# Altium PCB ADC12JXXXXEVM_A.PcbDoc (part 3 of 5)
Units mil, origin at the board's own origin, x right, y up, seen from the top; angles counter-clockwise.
Board outline 5739 x 2680 mil, 10 copper layers (Top Layer L1, Gnd-Plane - L2, Signals - L3, Gnd-Plane - L4, Pwr Plane - L5, Signals - L6, Gnd-Plane - L7, Signals - L8, Gnd-Plane - L9, Bottom Layer - L10), stack 57.8 mil thick; 582 components, 343 nets, 1924 pads, 1319 vias.

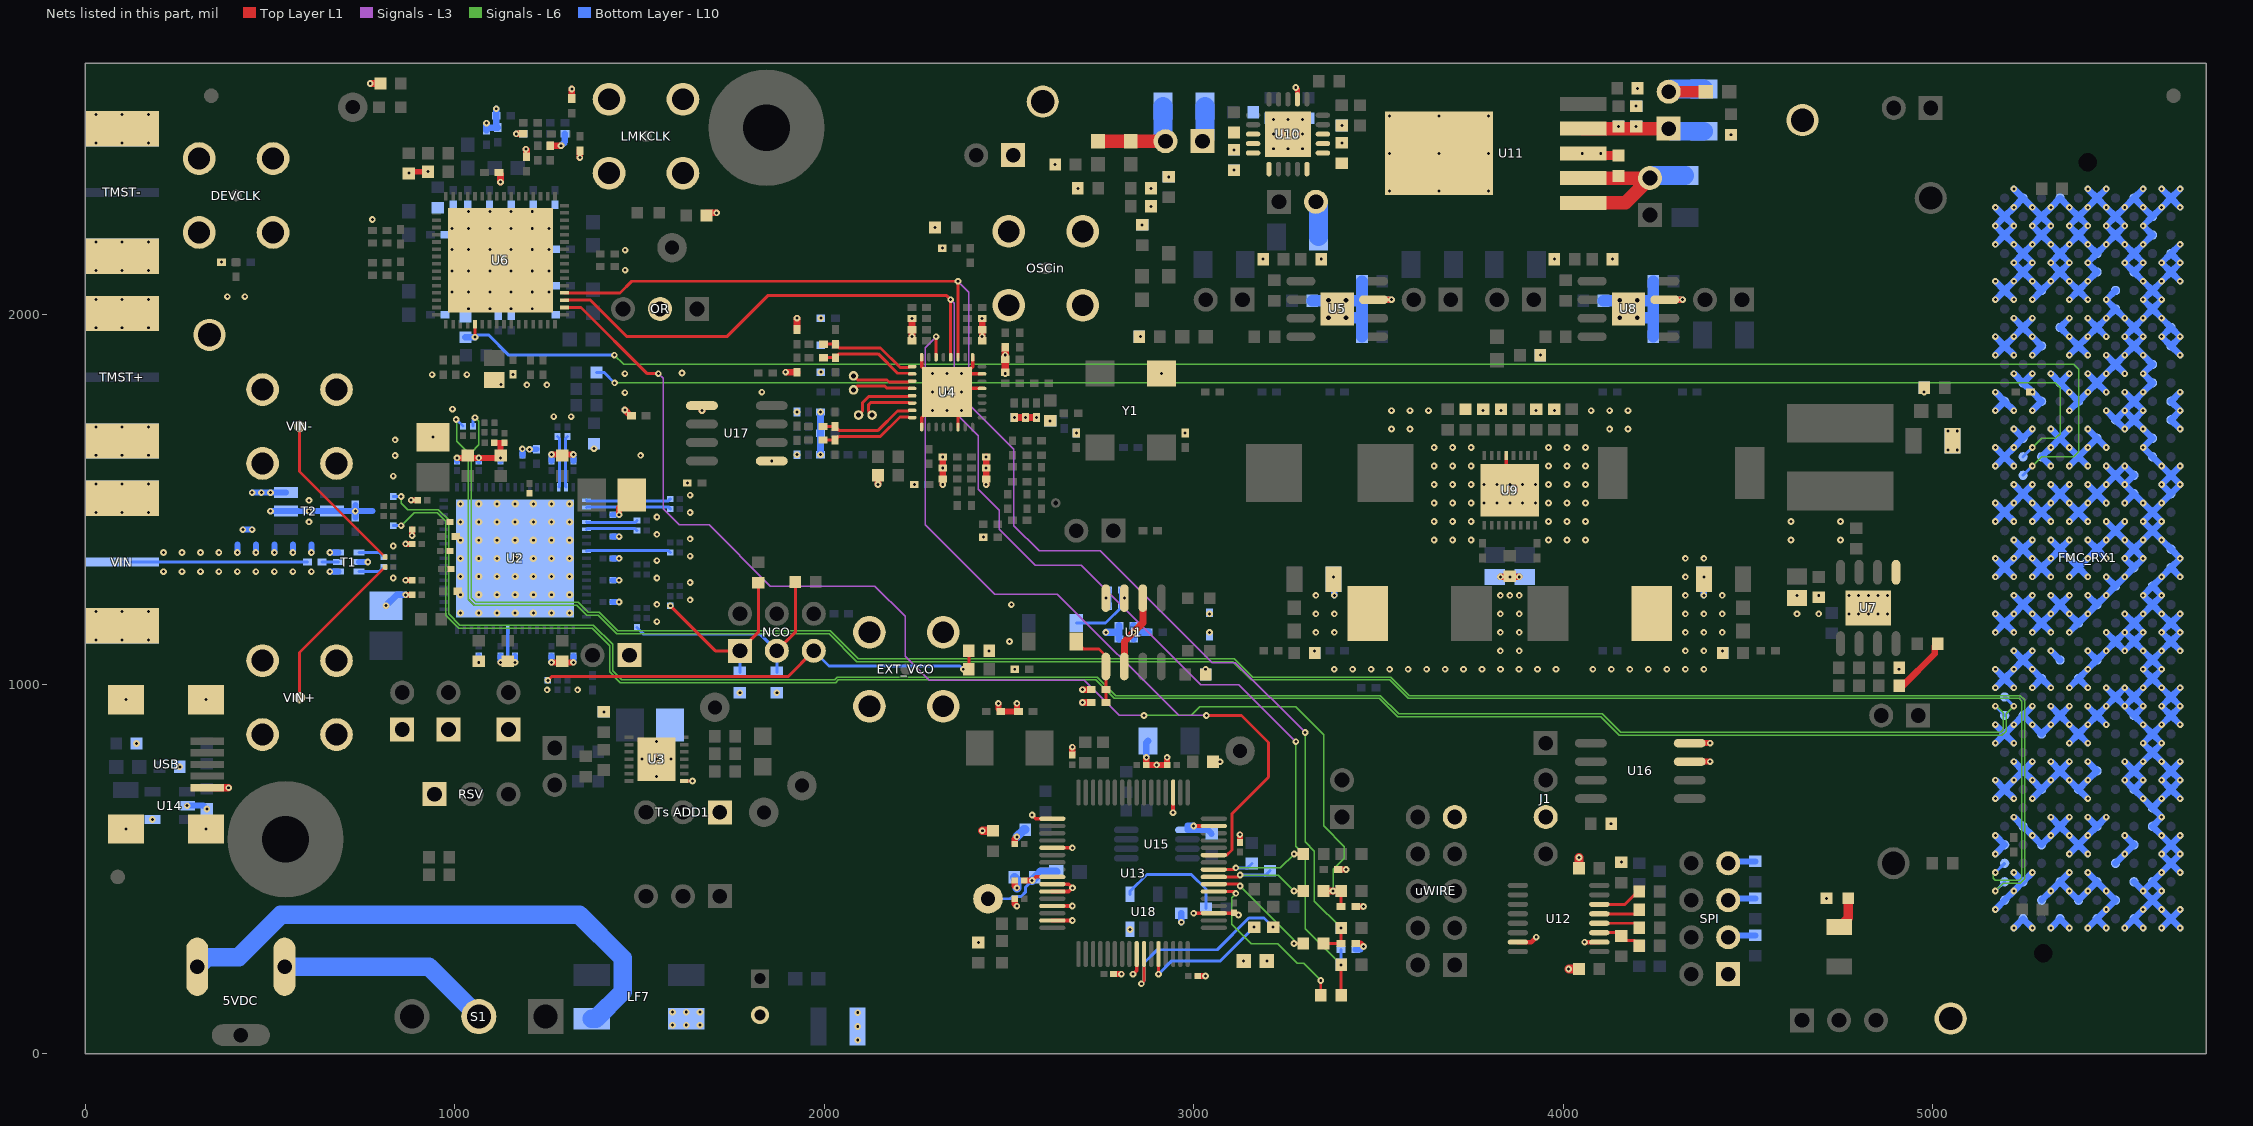
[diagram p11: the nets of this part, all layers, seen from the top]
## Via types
v1: diameter 18, hole 8, Top Layer L1 to Bottom Layer - L10, tented both sides, 1099 vias
v2: diameter 19.68, hole 7.87, Top Layer L1 to Bottom Layer - L10, 99 vias
v3: diameter 18, hole 8, Top Layer L1 to Bottom Layer - L10, tented bottom, 58 vias
v4: diameter 18, hole 8, Top Layer L1 to Bottom Layer - L10, tented top, 48 vias
v5: diameter 25.98, hole 12.99, Top Layer L1 to Bottom Layer - L10, tented top, 8 vias
v6: diameter 19.68, hole 7.87, Top Layer L1 to Bottom Layer - L10, tented top, 5 vias
v7: diameter 126, hole 106, Top Layer L1 to Bottom Layer - L10, tented top, 2 vias

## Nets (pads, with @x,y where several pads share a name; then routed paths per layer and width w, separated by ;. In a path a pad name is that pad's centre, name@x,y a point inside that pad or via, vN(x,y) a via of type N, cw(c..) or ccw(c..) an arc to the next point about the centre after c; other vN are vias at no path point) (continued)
FMC_DEVCLK_N: C93.2 FMC_RX1.K29 | length 4941.1
  Signals - L6 w4: v1(854.84,1507.44) 854.84,1489.67 872.56,1471.95 955.63,1471.95 983.08,1444.5 983.08,1190.03 1014.11,1159 1375.31,1159 1427,1107.31 1427,1036.2 1451.2,1012 2027.99,1012 2034.99,1019 2738,1019 2788,969 3505,969 3555,919 4105,919 4155,869 5183,869 5190,876 5190,923 5173,940 v3(5169,940)
  Bottom Layer - L10 w8: C93.2@833.57,1507.44 v1(854.84,1507.44) ; v3(5169,940) FMC_RX1.K29@5194,915
FMC_DEVCLK_P: C92.2 FMC_RX1.K28 | length 4941.6
  Signals - L6 w4: v1(854.84,1428.47) 890.32,1463.95 952.31,1463.95 975.08,1441.18 975.08,1186.71 1010.8,1151 1372,1151 1419,1104 1419,1032.89 1447.89,1004 2031.3,1004 2038.3,1011 2734.69,1011 2784.69,961 3501.69,961 3551.69,911 4101.69,911 4151.69,861 5186.31,861 5198,872.69 5198,919 v3(5219,940)
  Bottom Layer - L10 w8: C92.2@833.57,1428.47 v1(854.84,1428.47) ; FMC_RX1.K28@5194,965 v3(5219,940)
FMC_SYSREF_N: C91.2 FMC_RX1.K38 | length 5456.4
  Signals - L6 w4: v1(1054.96,1720.97) 1064.96,1710.97 1064.96,1647 1044.35,1626.39 1044.35,1233.09 1056.47,1220.97 1333.83,1220.97 1360.63,1194.16 1391.25,1194.16 1441.42,1144 2016.62,1144 2091.61,1069 3109,1069 3159,1019 3533,1019 3583,969 5236.31,969 5248,957.31 5248,472.69 5236.31,461 5190,461 v3(5169,440)
  Bottom Layer - L10 w8: C91.2@1048.93,1697.99 1048.93,1714.94 v1(1054.96,1720.97) ; v3(5169,440) FMC_RX1.K38@5194,465
FMC_SYSREF_P: C90.2 FMC_RX1.K37 | length 5456.2
  Signals - L6 w4: v1(1003.93,1715.99) 1005.9,1714.02 1005.9,1656.84 1036.35,1626.39 1036.35,1229.77 1053.16,1212.97 1330.51,1212.97 1357.32,1186.16 1387.94,1186.16 1438.1,1136 2013.3,1136 2088.3,1061 3105.69,1061 3155.69,1011 3529.69,1011 3579.69,961 5233,961 5240,954 5240,476 5233,469 5169,469 5163,475 5163,484 v3(5169,490)
  Bottom Layer - L10 w8: v1(1003.93,1715.99) C90.2@1021.93,1697.99 ; v3(5169,490) FMC_RX1.K37@5194,515
FTDI_ADC_SCLK: R109.2 U12.14 | length 122.5
  Top Layer L1 w8: U12.14@4097.24,403.91 4166.85,403.91 4201.44,438.5 R109.2@4205.44,438.5
FTDI_ADC_SCSB: R118.2 R123.1 U12.11 | length 123
  Top Layer L1 w8: U12.11@4097.24,327.14 4147.94,327.14 R123.1@4157,318.09 4168.56,306.53 4190.41,306.53 R118.2@4205.44,291.5
FTDI_ADC_SDI: R111.2 U12.13 | length 112.8
  Top Layer L1 w8: U12.13@4097.24,378.32 4194.26,378.32 R111.2@4205.44,389.5
FTDI_ADC_SDO: R110.2 U12.12 | length 113.3
  Top Layer L1 w8: U12.12@4097.24,352.73 4193.21,352.73 R110.2@4205.44,340.5
FTDI_LMK_CSB: R68.2 R130.2 U13.40 | length 347.3
  Top Layer L1 w8: U13.40@3053.98,478.16 3120.45,478.16 v1(3125.45,483.16) ; v1(3270.88,440) R68.2@3295.88,440
  Signals - L6 w4: v1(3125.45,483.16) 3227.72,483.16 v1(3270.88,440)
  Bottom Layer - L10 w8: v1(3125.45,483.16) 3194.25,483.16 R130.2@3206,494.9
FTDI_LMK_TRF_CLK: R115.2 U13.38 | length 494.8
  Top Layer L1 w8: U13.38@3053.98,438.79 3108.45,438.79 v1(3113.44,433.79) ; R115.2@3343.32,157.56 v1(3343.32,198)
  Signals - L6 w4: v1(3113.44,433.79) 3102,422.34 3102,350 3155,297 3227,297 3280,244 3297.32,244 v1(3343.32,198)
FTDI_LMK_TRF_DATA: R114.2 U13.39 | length 314.3
  Top Layer L1 w8: U13.39@3053.98,458.47 3120.45,458.47 v1(3125.45,453.47) ; v1(3270.88,298) R114.2@3295.88,298
  Signals - L6 w4: v1(3125.45,453.47) 3270.88,308.04 v1(3270.88,298)
FTDI_TRF_R1: U4.6 U13.43 | length 2136.4
  Top Layer L1 w8: U4.6@2302.71,1884.49 v1(2302.71,1940) ; v1(3034,915) 3129,915 3202,842 3202,748 3103,649 3103,551 3089.21,537.21 U13.43@3053.98,537.21
  Signals - L3 w4: v1(2302.71,1940) 2273.18,1910.47 2273.18,1430.82 2461,1243 2631,1243 2959,915 v1(3034,915)
FTDI_TRF_STROBE: R113.2 R131.2 U13.41 | length 308.3
  Top Layer L1 w8: U13.41@3053.98,497.84 3108.45,497.84 v1(3113.44,502.84) ; v1(3271.44,540) R113.2@3296.44,540
  Signals - L6 w4: v1(3113.44,502.84) 3234.28,502.84 v1(3271.44,540)
  Bottom Layer - L10 w8: v1(3113.44,502.84) 3145.25,502.84 R131.2@3157,514.59
FTDI_TS_SMBCLK: R125.2 U13.26 | length 552.5
  Top Layer L1 w8: v1(2858,189.03) 2865,196.03 U13.26@2865,269.5
  Bottom Layer - L10 w8: v1(2858,189.03) 2865,196.03 2865,245 2901,281 3063,281 3148.77,366.77 3189.8,366.77 v1(3214.56,342.01)
FTDI_TS_SMBDAT_IN: R124.2 U13.28 | length 365.7
  Top Layer L1 w8: v1(2904.37,215.03) U13.28@2904.37,269.5
  Bottom Layer - L10 w8: v1(2904.37,215.03) 2940.34,251 3071.99,251 v1(3163,342.01)
FTDI_TS_SMBDAT_OUT: R117.2 U18.4 | length 302.4
  Bottom Layer - L10 w8: U18.4@2827.29,430.85 2827.29,439.29 2873,485 2993,485 3032.7,445.3 R117.2@3032.7,392.13
GND: 12V.2 "Ts ADD1.1" C2.2 C8.2 C11.2 C16.1 C18.1 C19.1 C24.2 C25.2 C27.2 C39.2 C40.2 C41.1 C42.1 C43.1 C44.1 C45.1 C46.1 C47.1 C48.2 C49.2 C50.2 C51.1 C52.1 C53.1 C54.1 C55.1 C56.1 C57.1 C58.1 C59.2 C60.2 C61.2 C62.1 C63.1 C64.1 C65.1 C66.1 C67.1 C68.1 C69.1 C70.1 C71.1 C72.2 C73.1 C74.1 C77.2 C78.2 C79.2 C80.2 C81.2 C82.2 C85.1 C88.2 C102.2 C103.2 C104.2 C105.2 C106.2 C107.2 C108.2 C109.2 C110.2 C111.2 C114.1 C115.2 C116.2 C120.2 C121.2 C122.2 C124.2 C125.2 C126.2 C127.2 C128.2 C129.2 C130.2 C143.2 C144.2 C145.2 C146.2 C147.2 C150.2 C151.2 C152.2 C153.2 C155.2 C156.1 C157.1 C158.2 C159.2 C160.2 C161.2 C162.2 C163.2 C164.2 C165.2 C166.2 C167.2 C168.2 C171.2 C172.2 C173.2 C176.2 C177.2 C178.2 C179.2 C180.2 C181.2 C182.2 C183.2 C184.2 C185.2 C186.2 C187.2 C188.2 C189.2 C190.2 C191.2 C193.2 C194.2 C195.2 C196.2 C197.2 C198.2 C199.2 C202.2 C203.2 C204.2 C206.2 C207.2 C208.2 C209.2 C213.2 C215.2 C218.2 C228.2 C229.2 C230.2 C231.1 C232.2 C233.2 C234.2 C235.1 C236.2 C237.2 C238.2 C239.2 C240.2 C241.2 C242.2 C243.2 C250.1 C251.1 C252.2 C253.2 C254.2 C255.2 C256.2 C257.2 C258.1 C259.1 C260.1 C261.2 D11.2 D12.2 DEVCLK.2 DEVCLK.3 DEVCLK.4 DEVCLK.5 EXT_VCO.2 EXT_VCO.3 EXT_VCO.4 EXT_VCO.5 FMC_RX1.A1 FMC_RX1.A4 FMC_RX1.A5 FMC_RX1.A8 FMC_RX1.A9 FMC_RX1.A12 FMC_RX1.A13 FMC_RX1.A16 FMC_RX1.A17 FMC_RX1.A20 FMC_RX1.A21 FMC_RX1.A24 FMC_RX1.A25 FMC_RX1.A28 FMC_RX1.A29 FMC_RX1.A32 FMC_RX1.A33 FMC_RX1.A36 FMC_RX1.A37 FMC_RX1.A40 FMC_RX1.B2 FMC_RX1.B3 FMC_RX1.B6 FMC_RX1.B7 FMC_RX1.B10 FMC_RX1.B11 FMC_RX1.B14 FMC_RX1.B15 FMC_RX1.B18 FMC_RX1.B19 FMC_RX1.B22 FMC_RX1.B23 FMC_RX1.B26 FMC_RX1.B27 FMC_RX1.B30 FMC_RX1.B31 FMC_RX1.B34 FMC_RX1.B35 FMC_RX1.B38 FMC_RX1.B39 FMC_RX1.C1 FMC_RX1.C4 FMC_RX1.C5 FMC_RX1.C8 FMC_RX1.C9 FMC_RX1.C12 FMC_RX1.C13 FMC_RX1.C16 FMC_RX1.C17 FMC_RX1.C20 FMC_RX1.C21 FMC_RX1.C24 FMC_RX1.C25 FMC_RX1.C28 FMC_RX1.C29 FMC_RX1.C32 FMC_RX1.C33 FMC_RX1.C36 FMC_RX1.C38 FMC_RX1.C40 FMC_RX1.D2 FMC_RX1.D3 FMC_RX1.D6 FMC_RX1.D7 FMC_RX1.D10 FMC_RX1.D13 FMC_RX1.D16 FMC_RX1.D19 FMC_RX1.D22 FMC_RX1.D25 FMC_RX1.D28 FMC_RX1.D37 FMC_RX1.D39 FMC_RX1.E1 FMC_RX1.E4 FMC_RX1.E5 FMC_RX1.E8 FMC_RX1.E11 FMC_RX1.E14 FMC_RX1.E17 FMC_RX1.E20 FMC_RX1.E23 FMC_RX1.E26 FMC_RX1.E29 FMC_RX1.E32 FMC_RX1.E35 FMC_RX1.E38 FMC_RX1.E40 FMC_RX1.F2 FMC_RX1.F3 FMC_RX1.F6 FMC_RX1.F9 FMC_RX1.F12 FMC_RX1.F15 FMC_RX1.F18 FMC_RX1.F21 FMC_RX1.F24 FMC_RX1.F27 FMC_RX1.F30 FMC_RX1.F33 FMC_RX1.F36 FMC_RX1.F39 FMC_RX1.G1 FMC_RX1.G4 FMC_RX1.G5 FMC_RX1.G8 FMC_RX1.G11 FMC_RX1.G14 FMC_RX1.G17 FMC_RX1.G20 FMC_RX1.G23 FMC_RX1.G26 FMC_RX1.G29 FMC_RX1.G32 FMC_RX1.G35 FMC_RX1.G38 FMC_RX1.G40 FMC_RX1.H2 FMC_RX1.H3 FMC_RX1.H6 FMC_RX1.H9 FMC_RX1.H12 FMC_RX1.H15 FMC_RX1.H18 FMC_RX1.H21 FMC_RX1.H24 FMC_RX1.H27 FMC_RX1.H30 FMC_RX1.H33 FMC_RX1.H36 FMC_RX1.H39 FMC_RX1.J1 FMC_RX1.J4 FMC_RX1.J5 FMC_RX1.J8 FMC_RX1.J11 FMC_RX1.J14 FMC_RX1.J17 FMC_RX1.J20 FMC_RX1.J23 FMC_RX1.J26 FMC_RX1.J29 FMC_RX1.J32 FMC_RX1.J35 FMC_RX1.J38 FMC_RX1.J40 FMC_RX1.K2 FMC_RX1.K3 FMC_RX1.K6 FMC_RX1.K9 FMC_RX1.K12 FMC_RX1.K15 FMC_RX1.K18 FMC_RX1.K21 FMC_RX1.K24 FMC_RX1.K27 FMC_RX1.K30 FMC_RX1.K33 FMC_RX1.K36 FMC_RX1.K39 GND1.1 GND2.1 GND3.1 GND.1 J1.3 L23.2 LD.2 LF2.2 LF3.1 LF7.4 LMKCLK.2 LMKCLK.3 LMKCLK.4 LMKCLK.5 OR.2 OSCin.2 OSCin.3 OSCin.4 OSCin.5 R2.2 R3.1 R4.1 R5.1 R6.1 R10.2 R11.1 R12.1 R22.2 R23.2 R24.1 R26.1 R29.1 R30.1 R33.1 R36.1 R37.1 R45.1 R49.1 R50.2 R51.1 R56.1 R65.1 R76.1 R77.1 R86.1 R87.1 R88.1 R89.1 R90.1 R96.1 R104.1 R116.1 R122.1 R128.1 R129.1 R135.1 R139.1 R140.1 R141.1 R147.2 R152.2 R153.1 R158.1 R159.1 R165.1 RSV.1 SPI.1 SPI.3 SPI.5 SPI.7 T1.1 T1.3 T1.5 T2.1 T2.2 T2.5 TMST+.2 TMST+.3 TMST+.4 TMST+.5 TMST-.2 TMST-.3 TMST-.4 TMST-.5 U1.4 U2.61 U2.69 U3.8 U3.15 U4.1 U4.8 U4.17 U4.22 U4.29 U4.31 U4.33 U5.3 U5.9 U6.65 U7.5 U7.9 U8.3 U8.9 U9.5 U9.17 U10.12 U10.21 U11.3 U11.6 U12.7 U12.10 U16.3 U16.4 U17.1 U17.5 U18.3 uWIRE.9 VA12.1 VA19.1 Vbg.1 Vcmo.1 VD12.1 VIN+.2 VIN+.3 VIN+.4 VIN+.5 VIN-.2 VIN-.3 VIN-.4 VIN-.5 VIN.2 VIN.3 VIN.4 VIN.5 Y1.2 | length 24462.1
  Top Layer L1 w9: U3.8@1621.08,737.7 v1(1643.28,737.7)
  Top Layer L1 w9.45: U4.17@2263.34,1695.51 2263.34,1721.1 v2(2332.24,1790) ; U4.8@2263.34,1884.49 2263.34,1858.9 v2(2332.24,1790) ; U4.33@2342.08,1799.84 U4.29@2426.72,1799.84 ; U4.22@2361.76,1695.51 U4.33@2361.76,1760.47 ; U4.33@2381.45,1839.21 U4.31@2426.72,1839.21 ; U4.1@2401.13,1884.49 2401.13,1858.9 v2(2332.24,1790)
  Top Layer L1 w10: U9.5@3845.16,1618.49 3845.16,1553.53 U9.17@3855,1543.68
  Top Layer L1 w11.02: v2(2332.24,1790) U4.33@2361.76,1760.47
  Top Layer L1 w13: U12.7@3876.76,301.55 3913.03,301.55 v1(3926.48,315) ; v1(4057.68,301.55) U12.10@4097.24,301.55
  Top Layer L1 w13.5: v1(3275.77,2614.17) 3280.27,2609.67 U10.12@3280.27,2582.49
  Top Layer L1 w15: v1(876.3,2383.18) 879.86,2386.74 v1(927.74,2386.74)
  Top Layer L1 w16: v1(867.03,1241.58) C51.1@884.65,1241.57 ; v1(867.03,1280.95) C41.1@884.65,1280.94 ; v1(867.03,1379.37) C42.1@884.65,1379.37 ; v1(882.03,1497.48) C44.1@899.65,1497.48 ; v1(884.65,1401.47) C54.1@884.65,1418.74 ; v1(1005.91,1612) v1(1124.02,1612) ; R22.2@1106.99,1653 R23.2@1135,1653.01 ; v1(1124.02,1058.65) v1(1163.39,1058.65) ; C50.2@1124.02,1618.3 1124.02,1653 ; v1(1261.81,1058.65) v1(1320.87,1058.65) ; v1(1261.81,1621.35) v1(1320.87,1621.35) ; v1(1444.74,1458.11) 1444.74,1477.62 C72.2@1478.52,1511.4
  Top Layer L1 w16.5: R116.1@3390.93,498 v1(3411.98,498) ; R128.1@3437.81,298 3450.87,298 v1(3458.87,290) ; R104.1@3437.81,398 v1(3458.87,398) ; U16.3@4341.86,790 v1(4397.16,790) ; U16.4@4341.86,840 v1(4397.16,840)
  Top Layer L1 w18: v1(771.3,2625) R45.1@798.94,2625 ; C85.1@1119.68,2384 1123.56,2380.13 v1(1123.56,2358.32) ; v1(1166.43,2489) R50.2@1185.3,2489 ; v1(1192.16,2447.5) 1194,2445.65 C88.2@1194,2426.69 ; C114.1@1258.67,2456.68 v1(1287.54,2456.69) ; C259.1@1316.91,2584.24 v1(1316.91,2610.11) ; v1(1338.67,2424.26) R51.1@1338.67,2443.13 ; v1(1460.36,1741.48) 1475.84,1726 C215.2@1478.31,1726 ; v1(1668.84,1740) U17.5@1668.84,1753.5 ; R56.1@1681.06,2274.95 v1(1708.7,2274.95) ; v1(1895.23,1843.81) R36.1@1926.05,1843.81 ; R29.1@1926.05,1959.18 v1(1926.05,1990) ; v1(2145.44,1540) R152.2@2145.44,1565 ; C257.2@2237.35,1929.09 C256.2@2237.35,1959.09 v1(2237.35,1989.09) ; v1(2320.55,1540) C243.2@2320.55,1554.68 v1(2320.55,1614.68) ; C254.2@2427.12,1929.09 C253.2@2427.12,1959.09 v1(2427.12,1989.09) ; v1(2437.92,1540) C240.2@2437.92,1554.68 v1(2437.92,1614.68) ; v1(2514.33,1721.1) v1(2574.33,1721.1) ; v1(2698.82,950) R11.1@2722.63,950 ; v1(2698.82,985) C8.2@2722.63,985 ; U5.3@3486.43,2040 v1(3534.8,2040) ; v1(3829.47,1290) v1(3880.53,1290) ; U8.3@4274.43,2040 v1(4322.8,2040) ; R76.1@4908.56,995 4918,995 5005,1082 5005,1101.98 C162.2@5012.56,1109.54
  Top Layer L1 w19.68: C251.1@2489.65,1844 R30.1@2489.65,1911.41
  Top Layer L1 w24: v1(4014.37,229) R65.1@4042.12,229 ; C129.2@4042.12,502.06 v1(4042.12,530.79) ; U11.3@4053.22,2436 4059.13,2430.09 C196.2@4149,2430.09
  Bottom Layer - L10 w9: 1143.7,1058.65 U2.61@1143.7,1147.09
  Bottom Layer - L10 w16: v1(411.81,1356.14) 411.81,1378 ; v1(426.57,1417.95) v1(451.57,1417.95) ; v1(451.58,1517.95) T2.1@543.06,1517.95 ; v1(461.81,1356.14) 461.81,1378 ; v1(501.58,1467.95) 777,1467.95 ; v1(511.81,1356.14) 511.81,1378 ; v1(561.81,1356.14) 561.81,1378 ; v1(611.81,1356.14) 611.81,1378 ; v1(661.81,1304.17) T1.1@685.57,1304.17 ; v1(661.81,1356.14) T1.3@685.57,1356.14 ; C229.2@730.85,1451.14 v1(730.85,1467.95) C228.2@730.85,1484.76 ; T1.5@741.09,1330.16 v1(764.85,1330.16) ; C45.1@1005.91,1603.73 v1(1005.91,1612) ; v1(1064.96,1058.65) C47.1@1064.96,1076.27 ; C46.1@1064.96,1603.73 v1(1064.96,1612) ; C58.1@1124.02,1076.27 v1(1124.02,1058.65) v1(1163.39,1058.65) C57.1@1163.39,1076.27 ; C55.1@1124.02,1603.73 v1(1124.02,1612) ; C56.1@1183.07,1618.73 v1(1183.07,1636.35) ; v1(1202.16,1635.31) C16.1@1221,1635.31 ; v1(1261.81,1058.65) C62.1@1261.81,1076.27 ; C70.1@1261.81,1603.73 v1(1261.81,1621.35) ; v1(1320.87,1058.65) C63.1@1320.87,1076.27 ; C69.1@1320.87,1603.73 v1(1320.87,1621.35) ; C64.1@1427.12,1221.89 v1(1444.74,1221.89) ; C65.1@1427.12,1280.95 v1(1444.74,1280.94) ; C66.1@1427.12,1340 v1(1444.74,1340) ; C67.1@1427.12,1399.05 v1(1444.74,1399.05) ; C68.1@1427.12,1458.11 v1(1444.74,1458.11) ; SPI.3@4446,315 4451.12,320.12 R139.1@4519.44,320.12 ; SPI.5@4446,415 4451.12,420.12 R140.1@4519.44,420.12 ; SPI.7@4446,515 4451.12,520.12 R141.1@4519.44,520.12
  Bottom Layer - L10 w16.5: v1(2966,355.39) C213.2@2966,380.13 ; R129.1@3437.81,282 3450.87,282 v1(3458.87,290)
  Bottom Layer - L10 w18: v1(814,1212.13) 843.44,1241.58 v1(867.03,1241.58) ; C107.2@1085.92,2498.87 v1(1085.92,2517.74) ; C107.2@1085.92,2505.74 C104.2@1116.05,2505.74 1112.31,2509.47 C260.1@1112.32,2537.87 v1(1112.32,2556.74) ; v1(1166.43,2489) R159.1@1185.3,2489 ; v1(1287.54,2456.69) 1298.04,2467.19 R158.1@1298.04,2489 ; v1(3380,1240) C183.2@3380,1290 ; 3454.93,2040 v1(3534.8,2040) ; 4242.93,2040 v1(4322.8,2040) ; v1(4379.85,1240) v1(4379.85,1290) ; v1(5169,390) FMC_RX1.K39@5194,415 v1(5219,440) FMC_RX1.J38@5244,465 ; v1(5169,540) FMC_RX1.K36@5194,565 v1(5169,590) ; v1(5169,690) FMC_RX1.K33@5194,715 ; v1(5169,740) FMC_RX1.K33@5194,715 ; v1(5169,840) FMC_RX1.K30@5194,865 ; v1(5169,890) FMC_RX1.K30@5194,865 ; v1(5169,990) FMC_RX1.K27@5194,1015 ; v1(5169,1040) FMC_RX1.K27@5194,1015 ; v1(5169,1140) FMC_RX1.K24@5194,1165 ; v1(5169,1190) FMC_RX1.K24@5194,1165 ; v1(5169,1290) FMC_RX1.K21@5194,1315 ; v1(5169,1340) FMC_RX1.K21@5194,1315 ; v1(5169,1440) FMC_RX1.K18@5194,1465 ; v1(5169,1490) FMC_RX1.K18@5194,1465 ; v1(5169,1590) FMC_RX1.K15@5194,1615 ; v1(5169,1640) FMC_RX1.K15@5194,1615 ; v1(5169,1740) FMC_RX1.K12@5194,1765 ; v1(5169,1790) FMC_RX1.K12@5194,1765 ; v1(5169,1890) FMC_RX1.K9@5194,1915 ; v1(5169,1940) FMC_RX1.K9@5194,1915 ; v1(5169,2040) FMC_RX1.K6@5194,2065 ; v1(5169,2090) FMC_RX1.K6@5194,2065 ; v1(5169,2190) FMC_RX1.K3@5194,2215 ; v1(5169,2290) FMC_RX1.K2@5194,2265 ; v1(5219,340) FMC_RX1.J40@5244,365 v1(5269,340) ; v1(5219,490) FMC_RX1.J38@5244,465 ; v1(5219,640) FMC_RX1.J35@5244,615 v1(5269,590) FMC_RX1.H36@5294,565 v1(5319,590) FMC_RX1.G35@5344,615 ; v1(5219,690) FMC_RX1.K33@5194,715 ; v1(5219,790) FMC_RX1.J32@5244,765 ; v1(5219,840) FMC_RX1.K30@5194,865 ; v1(5219,990) FMC_RX1.K27@5194,1015 ; v1(5219,1090) FMC_RX1.J26@5244,1065 ; v1(5219,1140) FMC_RX1.K24@5194,1165 ; v1(5219,1240) FMC_RX1.J23@5244,1215 ; v1(5219,1290) FMC_RX1.K21@5194,1315 ; v1(5219,1390) FMC_RX1.J20@5244,1365 ; v1(5219,1440) FMC_RX1.K18@5194,1465 ; v1(5219,1540) FMC_RX1.J17@5244,1515 ; v1(5219,1590) FMC_RX1.K15@5194,1615 ; v1(5219,1690) FMC_RX1.J14@5244,1665 ; v1(5219,1740) FMC_RX1.K12@5194,1765 ; v1(5219,1840) FMC_RX1.J11@5244,1815 ; v1(5219,1890) FMC_RX1.K9@5194,1915 ; v1(5219,1990) FMC_RX1.J8@5244,1965 ; v1(5219,2040) FMC_RX1.K6@5194,2065 ; v1(5219,2340) FMC_RX1.J1@5244,2315 ; v1(5269,490) FMC_RX1.J38@5244,465 ; v1(5269,690) FMC_RX1.H33@5294,715 ; v1(5269,790) FMC_RX1.J32@5244,765 ; v1(5269,940) FMC_RX1.J29@5244,915 ; v1(5269,990) FMC_RX1.H27@5294,1015 ; v1(5269,1090) FMC_RX1.J26@5244,1065 ; v1(5269,1140) FMC_RX1.H24@5294,1165 ; v1(5269,1240) FMC_RX1.J23@5244,1215 ; v1(5269,1290) FMC_RX1.H21@5294,1315 ; v1(5269,1390) FMC_RX1.J20@5244,1365 ; v1(5269,1440) FMC_RX1.H18@5294,1465 ; v1(5269,1540) FMC_RX1.J17@5244,1515 ; v1(5269,1690) FMC_RX1.J14@5244,1665 ; v1(5269,1740) FMC_RX1.H12@5294,1765 v1(5269,1790) FMC_RX1.J11@5244,1815 ; v1(5269,1840) FMC_RX1.J11@5244,1815 ; v1(5269,1890) FMC_RX1.H9@5294,1915 v1(5269,1940) FMC_RX1.J8@5244,1965 ; v1(5269,1990) FMC_RX1.J8@5244,1965 ; v1(5269,2040) FMC_RX1.H6@5294,2065 ; FMC_RX1.H39@5294,415 v1(5319,440) FMC_RX1.G38@5344,465 ; v1(5319,340) FMC_RX1.G40@5344,365 v1(5369,340) ; v1(5319,640) FMC_RX1.G35@5344,615 ; v1(5319,790) FMC_RX1.G32@5344,765 ; v1(5319,940) FMC_RX1.G29@5344,915 ; v1(5319,990) FMC_RX1.H27@5294,1015 ; v1(5319,1090) FMC_RX1.G26@5344,1065 ; v1(5319,1140) FMC_RX1.H24@5294,1165 ; v1(5319,1240) FMC_RX1.G23@5344,1215 ; v1(5319,1290) FMC_RX1.H21@5294,1315 ; v1(5319,1390) FMC_RX1.G20@5344,1365 ; v1(5319,1440) FMC_RX1.H18@5294,1465 ; v1(5319,1540) FMC_RX1.G17@5344,1515 ; v1(5319,1590) FMC_RX1.H15@5294,1615 v1(5319,1640) FMC_RX1.G14@5344,1665 ; v1(5319,1690) FMC_RX1.G14@5344,1665 ; v1(5319,1840) FMC_RX1.G11@5344,1815 ; v1(5369,490) FMC_RX1.G38@5344,465 ; v1(5369,540) FMC_RX1.F36@5394,565 ; v1(5369,640) FMC_RX1.G35@5344,615 ; v1(5369,790) FMC_RX1.G32@5344,765 ; v1(5369,840) FMC_RX1.F30@5394,865 ; v1(5369,940) FMC_RX1.G29@5344,915 ; v1(5369,990) FMC_RX1.F27@5394,1015 ; v1(5369,1140) FMC_RX1.F24@5394,1165 ; v1(5369,1240) FMC_RX1.G23@5344,1215 ; v1(5369,1290) FMC_RX1.F21@5394,1315 ; v1(5369,1390) FMC_RX1.G20@5344,1365 ; v1(5369,1440) FMC_RX1.F18@5394,1465 ; v1(5369,1540) FMC_RX1.G17@5344,1515 ; v1(5369,1590) FMC_RX1.F15@5394,1615 ; v1(5369,1690) FMC_RX1.G14@5344,1665 ; v1(5369,1740) FMC_RX1.F12@5394,1765 ; v1(5369,1840) FMC_RX1.G11@5344,1815 ; v1(5369,1890) FMC_RX1.F9@5394,1915 ; v1(5369,1990) FMC_RX1.G8@5344,1965 v1(5369,1940) FMC_RX1.F9@5394,1915 ; v1(5369,2040) FMC_RX1.F6@5394,2065 ; FMC_RX1.F9@5392,1913 v1@5417,1938 ; v1(5419,340) FMC_RX1.E40@5444,365 ; v1(5419,490) FMC_RX1.E38@5444,465 ; v1(5419,540) FMC_RX1.F36@5394,565 ; v1(5419,640) FMC_RX1.E35@5444,615 ; v1(5419,690) FMC_RX1.F33@5394,715 ; v1(5419,790) FMC_RX1.E32@5444,765 v1(5419,740) FMC_RX1.F33@5394,715 ; v1(5419,840) FMC_RX1.F30@5394,865 ; v1(5419,940) FMC_RX1.E29@5444,915 ; v1(5419,990) FMC_RX1.F27@5394,1015 ; v1(5419,1090) FMC_RX1.E26@5444,1065 ; v1(5419,1240) FMC_RX1.E23@5444,1215 ; v1(5419,1290) FMC_RX1.F21@5394,1315 ; v1(5419,1390) FMC_RX1.E20@5444,1365 ; v1(5419,1440) FMC_RX1.F18@5394,1465 ; v1(5419,1540) FMC_RX1.E17@5444,1515 ; v1(5419,1590) FMC_RX1.F15@5394,1615 ; v1(5419,1690) FMC_RX1.E14@5444,1665 ; v1(5419,1840) FMC_RX1.E11@5444,1815 ; v1(5419,1890) FMC_RX1.F9@5394,1915 ; v1(5419,1940) FMC_RX1.E8@5444,1965 ; v1(5419,1990) FMC_RX1.E8@5444,1965 ; v1(5419,2040) FMC_RX1.F6@5394,2065 ; v1(5419,2340) FMC_RX1.E1@5444,2315 ; v1(5469,340) FMC_RX1.E40@5444,365 ; v1(5469,640) FMC_RX1.E35@5444,615 ; v1(5469,890) FMC_RX1.E29@5444,915 ; v1(5469,990) FMC_RX1.D28@5494,965 ; v1(5469,1140) FMC_RX1.D25@5494,1115 ; v1(5469,1290) FMC_RX1.D22@5494,1265 ; v1(5469,1340) FMC_RX1.E20@5444,1365 ; v1(5469,1440) FMC_RX1.D19@5494,1415 ; v1(5469,1490) FMC_RX1.E17@5444,1515 ; v1(5469,1590) FMC_RX1.D16@5494,1565 ; v1(5469,1640) FMC_RX1.E14@5444,1665 ; v1(5469,1740) FMC_RX1.D13@5494,1715 ; v1(5469,1790) FMC_RX1.E11@5444,1815 ; v1(5469,1890) FMC_RX1.D10@5494,1865 ; v1(5469,1940) FMC_RX1.E8@5444,1965 ; v1(5469,2340) FMC_RX1.E1@5444,2315 ; FMC_RX1.D37@5494,515 v1(5519,540) FMC_RX1.C36@5544,565 v1(5519,590) ; FMC_RX1.D6@5494,2065 v1(5469,2040) FMC_RX1.D7@5494,2015 ; v1(5519,340) FMC_RX1.C40@5544,365 ; v1(5519,790) FMC_RX1.C32@5544,765 ; v1(5519,1140) FMC_RX1.D25@5494,1115 ; v1(5519,1190) FMC_RX1.C24@5544,1165 ; v1(5519,1440) FMC_RX1.D19@5494,1415 ; v1(5519,1490) FMC_RX1.C17@5544,1515 ; v1(5519,1790) FMC_RX1.C12@5544,1765 ; v1(5519,1840) FMC_RX1.D10@5494,1865 ; FMC_RX1.C38@5544,465 v1(5569,440) ; FMC_RX1.C25@5545,1115 5520,1140 FMC_RX1.C24@5545,1165 ; v1(5569,340) FMC_RX1.C40@5544,365 ; v1(5569,1440) FMC_RX1.B18@5594,1465 ; v1(5569,2340) FMC_RX1.C1@5544,2315 ; v1@5573,1436 FMC_RX1.B19@5598,1411 ; v1(5619,340) FMC_RX1.A40@5644,365 ; v1(5619,2340) FMC_RX1.A1@5644,2315 ; v1(5669,340) FMC_RX1.A40@5644,365 ; v1(5669,390) FMC_RX1.A40@5644,365 ; v1(5669,490) FMC_RX1.A37@5644,515 ; v1(5669,590) FMC_RX1.A36@5644,565 ; v1(5669,690) FMC_RX1.A33@5644,715 ; v1(5669,790) FMC_RX1.A32@5644,765 ; v1(5669,890) FMC_RX1.A29@5644,915 ; v1(5669,990) FMC_RX1.A28@5644,965 ; v1(5669,1090) FMC_RX1.A25@5644,1115 ; v1(5669,1190) FMC_RX1.A24@5644,1165 ; v1(5669,1290) FMC_RX1.A21@5644,1315 ; v1(5669,1590) FMC_RX1.A16@5644,1565 ; v1(5669,1690) FMC_RX1.A13@5644,1715 v1(5669,1740) FMC_RX1.A12@5644,1765 v1(5669,1790) ; v1(5669,1890) FMC_RX1.A9@5644,1915 ; v1(5669,2090) FMC_RX1.A5@5644,2115 ; v1(5669,2190) FMC_RX1.A4@5644,2165 ; v1(5669,2290) FMC_RX1.A1@5644,2315 ; v1(5669,2340) FMC_RX1.A1@5644,2315 ; FMC_RX1.K33@5194,715 v1(5219,740) FMC_RX1.J32@5244,765 ; FMC_RX1.K30@5194,865 v1(5219,890) FMC_RX1.J29@5244,915 ; FMC_RX1.K27@5194,1015 v1(5219,1040) FMC_RX1.J26@5244,1065 ; FMC_RX1.K24@5194,1165 v1(5219,1190) FMC_RX1.J23@5244,1215 ; FMC_RX1.K21@5194,1315 v1(5219,1340) FMC_RX1.J20@5244,1365 ; FMC_RX1.K18@5194,1465 v1(5219,1490) FMC_RX1.J17@5244,1515 ; FMC_RX1.K15@5194,1615 v1(5219,1640) FMC_RX1.J14@5244,1665 ; FMC_RX1.K9@5194,1915 v1(5219,1940) FMC_RX1.J8@5244,1965 ; FMC_RX1.K6@5194,2065 v1(5219,2090) FMC_RX1.J5@5244,2115 ; FMC_RX1.K3@5194,2215 v1(5219,2240) FMC_RX1.K2@5194,2265 ; FMC_RX1.K3@5194,2215 v1(5219,2190) FMC_RX1.J4@5244,2165 ; FMC_RX1.K3@5194,2215 v1(5169,2240) FMC_RX1.K2@5194,2265 ; FMC_RX1.K2@5194,2265 v1(5219,2290) FMC_RX1.J1@5244,2315 ; FMC_RX1.J32@5244,765 v1(5269,740) FMC_RX1.H33@5294,715 ; FMC_RX1.J29@5244,915 v1(5269,890) FMC_RX1.H30@5294,865 v1(5319,890) FMC_RX1.G29@5344,915 ; FMC_RX1.J26@5244,1065 v1(5269,1040) FMC_RX1.H27@5294,1015 ; FMC_RX1.J23@5244,1215 v1(5269,1190) FMC_RX1.H24@5294,1165 ; FMC_RX1.J20@5244,1365 v1(5269,1340) FMC_RX1.H21@5294,1315 ; FMC_RX1.J17@5244,1515 v1(5269,1490) FMC_RX1.H18@5294,1465 ; FMC_RX1.J5@5244,2115 v1(5269,2140) FMC_RX1.J4@5244,2165 ; FMC_RX1.J5@5244,2115 v1(5219,2140) FMC_RX1.J4@5244,2165 ; FMC_RX1.J5@5244,2115 v1(5269,2090) FMC_RX1.H6@5294,2065 ; FMC_RX1.J4@5244,2165 v1(5269,2190) FMC_RX1.H3@5294,2215 ; FMC_RX1.J1@5244,2315 v1(5269,2290) FMC_RX1.H2@5294,2265 ; FMC_RX1.H33@5294,715 v1(5319,740) FMC_RX1.G32@5344,765 ; FMC_RX1.H24@5294,1165 v1(5319,1190) FMC_RX1.G23@5344,1215 ; FMC_RX1.H21@5294,1315 v1(5319,1340) FMC_RX1.G20@5344,1365 ; FMC_RX1.H18@5294,1465 v1(5319,1490) FMC_RX1.G17@5344,1515 ; FMC_RX1.H6@5294,2065 v1(5319,2090) FMC_RX1.G5@5344,2115 ; FMC_RX1.H3@5294,2215 v1(5269,2240) FMC_RX1.H2@5294,2265 ; FMC_RX1.H3@5294,2215 v1(5319,2190) FMC_RX1.G4@5344,2165 ; FMC_RX1.H3@5294,2215 v1(5319,2240) FMC_RX1.H2@5294,2265 ; FMC_RX1.H2@5294,2265 v1(5319,2290) FMC_RX1.G1@5344,2315 v1(5369,2290) FMC_RX1.F2@5394,2265 ; FMC_RX1.G38@5344,465 v1(5369,440) FMC_RX1.F39@5394,415 v1(5419,440) FMC_RX1.E38@5444,465 ; FMC_RX1.G35@5344,615 v1(5369,590) FMC_RX1.F36@5394,565 ; FMC_RX1.G32@5344,765 v1(5369,740) FMC_RX1.F33@5394,715 ; FMC_RX1.G29@5344,915 v1(5369,890) FMC_RX1.F30@5394,865 ; FMC_RX1.G23@5344,1215 v1(5369,1190) FMC_RX1.F24@5394,1165 ; FMC_RX1.G20@5344,1365 v1(5369,1340) FMC_RX1.F21@5394,1315 ; FMC_RX1.G17@5344,1515 v1(5369,1490) FMC_RX1.F18@5394,1465 ; FMC_RX1.G14@5344,1665 v1(5369,1640) FMC_RX1.F15@5394,1615 ; FMC_RX1.G11@5344,1815 v1(5369,1790) FMC_RX1.F12@5394,1765 ; FMC_RX1.G5@5344,2115 v1(5369,2140) FMC_RX1.G4@5344,2165 ; FMC_RX1.G5@5344,2115 v1(5319,2140) FMC_RX1.G4@5344,2165 ; FMC_RX1.G5@5344,2115 v1(5369,2090) FMC_RX1.F6@5394,2065 ; FMC_RX1.G4@5344,2165 v1(5369,2190) FMC_RX1.F3@5394,2215 ; FMC_RX1.F36@5394,565 v1(5419,590) FMC_RX1.E35@5444,615 ; FMC_RX1.F30@5394,865 v1(5419,890) FMC_RX1.E29@5444,915 ; FMC_RX1.F27@5394,1015 v1(5419,1040) FMC_RX1.E26@5444,1065 ; FMC_RX1.F24@5394,1165 v1(5419,1190) FMC_RX1.E23@5444,1215 ; FMC_RX1.F21@5394,1315 v1(5419,1340) FMC_RX1.E20@5444,1365 ; FMC_RX1.F18@5394,1465 v1(5419,1490) FMC_RX1.E17@5444,1515 ; FMC_RX1.F15@5394,1615 v1(5419,1640) FMC_RX1.E14@5444,1665 ; FMC_RX1.F12@5394,1765 v1(5419,1790) FMC_RX1.E11@5444,1815 ; FMC_RX1.F6@5394,2065 v1(5419,2090) FMC_RX1.E5@5444,2115 v1(5419,2140) FMC_RX1.E4@5444,2165 ; FMC_RX1.F3@5394,2215 v1(5419,2240) FMC_RX1.F2@5394,2265 ; FMC_RX1.F3@5394,2215 v1(5369,2240) FMC_RX1.F2@5394,2265 ; FMC_RX1.F3@5394,2215 v1(5419,2190) FMC_RX1.E4@5444,2165 ; FMC_RX1.F2@5394,2265 v1(5419,2290) FMC_RX1.E1@5444,2315 ; FMC_RX1.E40@5444,365 v1(5469,390) FMC_RX1.D39@5494,415 v1(5469,440) FMC_RX1.E38@5444,465 ; FMC_RX1.E29@5444,915 v1(5469,940) FMC_RX1.D28@5494,965 ; FMC_RX1.E26@5444,1065 v1(5469,1090) FMC_RX1.D25@5494,1115 ; FMC_RX1.E23@5444,1215 v1(5469,1240) FMC_RX1.D22@5494,1265 ; FMC_RX1.E20@5444,1365 v1(5469,1390) FMC_RX1.D19@5494,1415 ; FMC_RX1.E17@5444,1515 v1(5469,1540) FMC_RX1.D16@5494,1565 ; FMC_RX1.E11@5444,1815 v1(5469,1840) FMC_RX1.D10@5494,1865 ; FMC_RX1.E8@5444,1965 v1(5469,1990) FMC_RX1.D7@5494,2015 ; FMC_RX1.E4@5444,2165 v1(5469,2190) FMC_RX1.D3@5494,2215 ; FMC_RX1.E1@5444,2315 v1(5469,2290) FMC_RX1.D2@5494,2265 ; FMC_RX1.D28@5494,965 v1(5519,990) FMC_RX1.C28@5544,965 ; FMC_RX1.D28@5494,965 v1(5519,940) ; FMC_RX1.D25@5494,1115 v1(5519,1090) FMC_RX1.C25@5544,1115 ; FMC_RX1.D22@5494,1265 v1(5519,1290) FMC_RX1.C21@5544,1315 ; FMC_RX1.D19@5494,1415 v1(5519,1390) FMC_RX1.C20@5544,1365 ; FMC_RX1.D16@5494,1565 v1(5519,1590) FMC_RX1.C16@5544,1565 v1(5519,1540) ; FMC_RX1.D16@5494,1565 v1(5519,1540) ; FMC_RX1.D13@5494,1715 v1(5519,1690) FMC_RX1.C13@5544,1715 ; FMC_RX1.D13@5494,1715 v1(5519,1740) ; FMC_RX1.D10@5494,1865 v1(5519,1890) FMC_RX1.C9@5544,1915 ; FMC_RX1.D7@5494,2015 v1(5519,1990) FMC_RX1.C8@5544,1965 ; FMC_RX1.D3@5494,2215 v1(5469,2240) FMC_RX1.D2@5494,2265 ; FMC_RX1.D3@5494,2215 v1(5519,2190) FMC_RX1.C4@5544,2165 ; FMC_RX1.D3@5494,2215 v1(5519,2240) FMC_RX1.D2@5494,2265 ; FMC_RX1.D2@5494,2265 v1(5519,2290) FMC_RX1.C1@5544,2315 ; v1(5519,940) FMC_RX1.C29@5544,915 ; v1(5519,940) FMC_RX1.C28@5544,965 ; v1(5519,1540) FMC_RX1.C17@5544,1515 ; v1(5519,1740) FMC_RX1.C12@5544,1765 ; v1(5519,1740) FMC_RX1.C13@5544,1715 ; FMC_RX1.C40@5544,365 v1(5569,390) FMC_RX1.B39@5594,415 ; FMC_RX1.C33@5544,715 v1(5519,740) FMC_RX1.C32@5544,765 ; FMC_RX1.C33@5544,715 v1(5569,740) FMC_RX1.C32@5544,765 ; FMC_RX1.C33@5544,715 v1(5569,690) FMC_RX1.B34@5594,665 ; FMC_RX1.C32@5544,765 v1(5569,790) FMC_RX1.B31@5594,815 ; FMC_RX1.C29@5544,915 v1(5569,940) FMC_RX1.C28@5544,965 ; FMC_RX1.C29@5544,915 v1(5569,890) FMC_RX1.B30@5594,865 ; FMC_RX1.C28@5544,965 v1(5569,990) FMC_RX1.B27@5594,1015 ; FMC_RX1.C25@5544,1115 v1(5569,1140) FMC_RX1.C24@5544,1165 ; FMC_RX1.C25@5544,1115 v1(5569,1090) FMC_RX1.B26@5594,1065 ; FMC_RX1.C24@5544,1165 v1(5569,1190) FMC_RX1.B23@5594,1215 ; FMC_RX1.C21@5544,1315 v1(5569,1340) FMC_RX1.C20@5544,1365 ; FMC_RX1.C21@5544,1315 v1(5519,1340) FMC_RX1.C20@5544,1365 ; FMC_RX1.C20@5544,1365 v1(5569,1390) FMC_RX1.B19@5594,1415 ; FMC_RX1.C17@5544,1515 v1(5569,1490) FMC_RX1.B18@5594,1465 ; FMC_RX1.C13@5544,1715 v1(5569,1690) FMC_RX1.B14@5594,1665 v1(5569,1640) FMC_RX1.B15@5594,1615 v1(5619,1590) FMC_RX1.A16@5644,1565 ; FMC_RX1.C13@5544,1715 v1(5569,1740) FMC_RX1.C12@5544,1765 ; FMC_RX1.C12@5544,1765 v1(5569,1790) FMC_RX1.B11@5594,1815 v1(5569,1840) FMC_RX1.B10@5594,1865 v1(5569,1890) FMC_RX1.C9@5544,1915 ; FMC_RX1.C9@5544,1915 v1(5519,1940) FMC_RX1.C8@5544,1965 ; FMC_RX1.C9@5544,1915 v1(5569,1940) FMC_RX1.C8@5544,1965 ; FMC_RX1.C8@5544,1965 v1(5569,1990) FMC_RX1.B7@5594,2015 ; FMC_RX1.C5@5544,2115 v1(5569,2090) FMC_RX1.B6@5594,2065 ; FMC_RX1.C5@5544,2115 v1(5519,2140) FMC_RX1.C4@5544,2165 ; FMC_RX1.C5@5544,2115 v1(5569,2140) FMC_RX1.C4@5544,2165 ; FMC_RX1.C4@5544,2165 v1(5569,2190) FMC_RX1.B3@5594,2215 v1(5569,2240) FMC_RX1.B2@5594,2265 ; FMC_RX1.C1@5544,2315 v1(5569,2290) FMC_RX1.B2@5594,2265 ; v1(5569,440) FMC_RX1.B39@5594,415 ; v1(5569,440) FMC_RX1.B38@5594,465 ; FMC_RX1.B39@5594,415 v1(5619,390) FMC_RX1.A40@5644,365 ; FMC_RX1.B39@5594,415 v1(5619,440) FMC_RX1.B38@5594,465 ; FMC_RX1.B38@5594,465 v1(5619,490) FMC_RX1.A37@5644,515 ; FMC_RX1.B34@5594,665 v1(5619,640) FMC_RX1.B35@5594,615 v1(5619,590) FMC_RX1.A36@5644,565 ; FMC_RX1.B34@5594,665 v1(5619,690) FMC_RX1.A33@5644,715 ; FMC_RX1.B31@5594,815 v1(5619,790) FMC_RX1.A32@5644,765 ; FMC_RX1.B31@5594,815 v1(5619,840) FMC_RX1.B30@5594,865 ; FMC_RX1.B31@5594,815 v1(5569,840) FMC_RX1.B30@5594,865 ; FMC_RX1.B30@5594,865 v1(5619,890) FMC_RX1.A29@5644,915 ; FMC_RX1.B27@5594,1015 v1(5619,1040) FMC_RX1.B26@5594,1065 ; FMC_RX1.B27@5594,1015 v1(5619,990) FMC_RX1.A28@5644,965 ; FMC_RX1.B27@5594,1015 v1(5569,1040) FMC_RX1.B26@5594,1065 ; FMC_RX1.B26@5594,1065 v1(5619,1090) FMC_RX1.A25@5644,1115 ; FMC_RX1.B23@5594,1215 v1(5619,1190) FMC_RX1.A24@5644,1165 ; FMC_RX1.B23@5594,1215 v1(5619,1240) FMC_RX1.B22@5594,1265 ; FMC_RX1.B23@5594,1215 v1(5569,1240) FMC_RX1.B22@5594,1265 ; FMC_RX1.B22@5594,1265 v1(5619,1290) FMC_RX1.A21@5644,1315 ; FMC_RX1.B19@5594,1415 v1(5619,1390) FMC_RX1.A20@5644,1365 v1(5669,1340) FMC_RX1.A21@5644,1315 ; FMC_RX1.B19@5594,1415 v1(5619,1440) FMC_RX1.B18@5594,1465 ; FMC_RX1.B18@5594,1465 v1(5619,1490) FMC_RX1.A17@5644,1515 ; FMC_RX1.B7@5594,2015 v1(5569,2040) FMC_RX1.B6@5594,2065 ; FMC_RX1.B7@5594,2015 v1(5619,2040) FMC_RX1.B6@5594,2065 ; FMC_RX1.B7@5594,2015 v1(5619,1990) FMC_RX1.A8@5644,1965 ; FMC_RX1.B6@5594,2065 v1(5619,2090) FMC_RX1.A5@5644,2115 ; FMC_RX1.B2@5594,2265 v1(5619,2290) FMC_RX1.A1@5644,2315 ; FMC_RX1.A37@5644,515 v1(5619,540) FMC_RX1.A36@5644,565 ; FMC_RX1.A37@5644,515 v1(5669,540) FMC_RX1.A36@5644,565 ; FMC_RX1.A33@5644,715 v1(5669,740) FMC_RX1.A32@5644,765 ; FMC_RX1.A33@5644,715 v1(5619,740) FMC_RX1.A32@5644,765 ; FMC_RX1.A29@5644,915 v1(5669,940) FMC_RX1.A28@5644,965 ; FMC_RX1.A29@5644,915 v1(5619,940) FMC_RX1.A28@5644,965 ; FMC_RX1.A25@5644,1115 v1(5669,1140) FMC_RX1.A24@5644,1165 ; FMC_RX1.A25@5644,1115 v1(5619,1140) FMC_RX1.A24@5644,1165 ; FMC_RX1.A17@5644,1515 v1(5669,1540) FMC_RX1.A16@5644,1565 ; FMC_RX1.A17@5644,1515 v1(5619,1540) FMC_RX1.A16@5644,1565 ; FMC_RX1.A9@5644,1915 v1(5669,1940) FMC_RX1.A8@5644,1965 ; FMC_RX1.A9@5644,1915 v1(5619,1940) FMC_RX1.A8@5644,1965 ; FMC_RX1.A5@5644,2115 v1(5619,2140) FMC_RX1.A4@5644,2165 ; FMC_RX1.A5@5644,2115 v1(5669,2140) FMC_RX1.A4@5644,2165
  Bottom Layer - L10 w19.5: v1(2762,1140) 2797.63,1140 ; C2.2@2767.31,1210.67 R3.1@2767.32,1254.36 ; R12.1@2797.63,1122 C11.2@2797.63,1158
  Bottom Layer - L10 w19.68: v1(1989.68,1620.81) v1(1989.68,1736.18)
  Bottom Layer - L10 w31.5: R49.1@3320.56,2037.44 3454.93,2037.44 ; v5(3364.38,2038.62) v5(3364.38,1991.38) 3454.93,1991.38 ; v5(3411.62,1991.38) v5(3411.62,2038.62) ; C128.2@3454.93,1940 C127.2@3454.93,2090 ; R77.1@4108.56,2037.44 4242.93,2037.44 ; v5(4152.38,2038.62) v5(4152.38,1991.38) 4242.93,1991.38 ; v5(4199.62,1991.38) v5(4199.62,2038.62) ; C161.2@4242.93,1940 C160.2@4242.93,2090
  other v1: 2090.45,36.28 2090.45,73.49 1589.24,76.96 1626.46,76.96 1663.67,76.96 2090.45,110.7 1589.24,112.01 1626.46,112.01 1663.67,112.01 3197.5,251 2827.29,335.96 4711.94,420 4157,517.87 4129.26,622 1403.28,924.59 1771.5,976.44 1871.5,976.44 1250.02,984.2 1332.65,984.2 2515.31,1040 3032.05,1040 3379.85,1040 3429.85,1040 3479.85,1040 3529.85,1040 3579.85,1040 3629.85,1040 3679.85,1040 3729.85,1040 3779.85,1040 3829.85,1040 3879.85,1040 3929.85,1040 3979.85,1040 4079.85,1040 4129.85,1040 4179.85,1040 4229.85,1040 4279.85,1040 4329.85,1040 4379.85,1040 4908.56,1040 2446.06,1090 3326.97,1090 3829.47,1090 3880.53,1090 4329.85,1090 4379.85,1090 4431.03,1090 2501,1115 3042.53,1140 3330,1140 3380,1140 3829.47,1140 3880.53,1140 4329.85,1140 4379.85,1140 4429.85,1140 1547,1168.84 3042.53,1190 3330,1190 3380,1190 3829.47,1190 3880.53,1190 4329.85,1190 4379.85,1190 4429.85,1190 4632,1190 4691,1190 2506,1215 1547,1215.89 1637,1227.89 2762,1232.52 3330,1240 3829.47,1240 3855,1240 3880.53,1240 4329.85,1240 4429.85,1240 4632,1240 4691,1240 1637,1274.95 833.57,1286.84 1547,1286.95 3378.15,1290 3855,1290 4329.85,1290 211.81,1304.17 261.81,1304.17 311.81,1304.17 361.81,1304.17 411.81,1304.17 461.81,1304.17 511.81,1304.17 561.81,1304.17 611.81,1304.17 1547,1334 4329.85,1340 4379.85,1340 1637,1346 211.81,1356.14 261.81,1356.14 311.81,1356.14 361.81,1356.14 833.57,1373.47 3650.39,1390 3700.39,1390 3750.39,1390 3959.61,1390 4009.61,1390 4059.61,1390 4616,1390 4750,1390 1637,1393.06 2430.31,1397.5 1547,1405.06 605.65,1438.95 3650.39,1440 3700.39,1440 3750.39,1440 3959.61,1440 4009.61,1440 4059.61,1440 4616,1440 4750,1440 1547,1452.11 1637,1464.11 605.65,1467.95 3650.39,1490 3700.39,1490 3750.39,1490 3785.26,1490 3820.13,1490 3855,1490 3889.87,1490 3924.74,1490 3959.61,1490 4009.61,1490 4059.61,1490 605.65,1496.95 1637,1511.17 476.58,1517.95 501.58,1517.95 2243.65,1540 3650.39,1540 3700.39,1540 3750.39,1540 3785.26,1540 3820.13,1540 3855,1540 3889.87,1540 3924.74,1540 3959.61,1540 4009.61,1540 4059.61,1540 1629.47,1544.09 833.57,1562.43 2320.55,1584.68 2437.92,1584.68 3650.39,1590 3700.39,1590 3750.39,1590 3959.61,1590 4009.61,1590 4059.61,1590 1857.82,1603.5 838.82,1618.62 1503,1619 1926.05,1620.81 5040.5,1633.3 5065.8,1633.3 1376.64,1637 3650.39,1640 3700.39,1640 3750.39,1640 3959.61,1640 4009.61,1640 4059.61,1640 838.82,1660.67 941,1668.13 2682,1679.37 2976.47,1679.37 5040.5,1684.2 5065.8,1684.2 3535,1690 3585,1690 4125,1690 4175,1690 2611.33,1712.23 2544.33,1721.1 1267.81,1723.61 1314.86,1723.61 1926.05,1736.18 3535,1740 3585,1740 3635,1740 3783,1740 3831,1740 3926,1740 3976,1740 4075,1740 4125,1740 4175,1740 993.91,1743.81 1460.36,1788.53 1831,1790 4976.38,1790 1194.96,1809.5 1249.01,1809.5 1124.92,1811 938.95,1837.32 1032.58,1837.31 1157.3,1838.05 1460.36,1840 2489.65,1840 2911.91,1840 1615,1841.77 1990.68,1843.81 2489.65,1890 3937.56,1890 2237.35,1940 2427.12,1940 2855,1940 1990.68,1990 384.47,2048.5 432.15,2048.5 1461.06,2119.97 368.94,2141.68 3187.44,2150 3344.69,2150 3975.44,2150 4132.69,2150 1461.06,2174.02 2319.31,2179.37 2299.63,2235.37 2860,2242.56 777.1,2257 2884.12,2292.5 3529.79,2334.81 3663.46,2334.81 3797.13,2334.81 2685.88,2341.5 2884.12,2341.5 2932,2372.62 3108.68,2390.44 2624.44,2406.01 3529.79,2436 3663.46,2436 3797.13,2436 4051,2436 4101,2436 3400.68,2464.56 4453.5,2486.37 3400.68,2511.44 3529.79,2537.19 3663.46,2537.19 3797.13,2537.19 4197,2563.95 4200.56,2612
  other v2: 1015.75,1192.36 1064.96,1192.36 1114.17,1192.36 1163.39,1192.36 1212.6,1192.36 1261.81,1192.36 1311.02,1192.36 1015.75,1241.57 1064.96,1241.57 1114.17,1241.57 1163.39,1241.57 1212.6,1241.57 1261.81,1241.57 1311.02,1241.57 1015.75,1290.79 1064.96,1290.79 1114.17,1290.79 1163.39,1290.79 1212.6,1290.79 1261.81,1290.79 1311.02,1290.79 1015.75,1340 1064.96,1340 1114.17,1340 1163.39,1340 1212.6,1340 1261.81,1340 1311.02,1340 1015.75,1389.21 1064.96,1389.21 1114.17,1389.21 1163.39,1389.21 1212.6,1389.21 1261.81,1389.21 1311.02,1389.21 1015.75,1438.43 1064.96,1438.43 1114.17,1438.43 1163.39,1438.43 1212.6,1438.43 1261.81,1438.43 1311.02,1438.43 1015.75,1487.64 1064.96,1487.64 1114.17,1487.64 1163.39,1487.64 1212.6,1487.64 1261.81,1487.64 1311.02,1487.64 2292.87,1740 2332.24,1740 2371.61,1740 2292.87,1790 2371.61,1790 2292.87,1840 2332.24,1840 2371.61,1840 1037.34,2015.5 1094.82,2015.5 1152.3,2015.5 1209.78,2015.5 992.06,2060.78 1037.34,2060.78 1094.82,2060.78 1152.3,2060.78 1209.78,2060.78 1255.06,2060.78 992.06,2118.26 1037.34,2118.26 1094.82,2118.26 1152.3,2118.26 1209.78,2118.26 1255.06,2118.26 992.06,2175.74 1037.34,2175.74 1094.82,2175.74 1152.3,2175.74 1209.78,2175.74 1255.06,2175.74 992.06,2233.22 1037.34,2233.22 1094.82,2233.22 1152.3,2233.22 1209.78,2233.22 1255.06,2233.22 1037.34,2278.5 1094.82,2278.5 1152.3,2278.5 1209.78,2278.5 3215.3,2448.63 3254.68,2448.63 3294.05,2448.63 3215.3,2488 3254.68,2488 3294.05,2488 3215.3,2527.37 3254.68,2527.37 3294.05,2527.37
  other v4: 29,1119.16 100,1119.16 171,1119.16 4772.98,1190 4798.99,1190 4825,1190 4851.01,1190 4877.02,1190 29,1196.16 100,1196.16 171,1196.16 4772.98,1240 4798.99,1240 4825,1240 4851.01,1240 4877.02,1240 29,1464.16 100,1464.16 171,1464.16 29,1541.16 100,1541.16 171,1541.16 29,1619.16 100,1619.16 171,1619.16 29,1696.16 100,1696.16 171,1696.16 29,1964.16 100,1964.16 171,1964.16 29,2041.16 100,2041.16 171,2041.16 29,2119.16 100,2119.16 171,2119.16 29,2196.16 100,2196.16 171,2196.16 29,2464.16 100,2464.16 171,2464.16 29,2541.16 100,2541.16 171,2541.16
  other v6: 1546.28,749.51 1506.91,796.76 1546.28,796.76 1585.65,796.76 1546.28,844
GND2: C118.2 C119.2 C131.2 C132.2 C133.2 C134.2 C135.2 C136.2 C137.2 C138.2 C139.2 C140.2 C141.2 C142.2 C200.2 C201.2 C205.2 C210.2 C211.2 C212.1 C214.2 L23.1 R67.1 R112.1 U13.1 U13.5 U13.10 U13.11 U13.13 U13.15 U13.25 U13.35 U13.47 U13.51 U14.2 U14.4 U15.5 USB.5 USB.6 USB.7 USB.8 USB.9 | length 1322.1
  Top Layer L1 w10: v1(2562.5,645.48) 2572.34,635.64 U13.1@2616.97,635.64 ; U13.15@2616.97,360.05 v1(2671,360.05) ; U13.13@2616.97,399.42 v1(2671,399.42) ; U13.11@2616.97,438.79 2661.59,438.79 v1(2671.44,448.63) 2661.59,458.47 U13.10@2616.97,458.47 ; U13.5@2616.97,556.9 v1(2671,556.9) ; v1(2835.47,215.03) 2845.31,224.87 U13.25@2845.31,269.5 ; v1(2943.74,652.04) U13.51@2943.74,706.5 ; v1(2999.51,379.73) U13.35@3053.98,379.73 C134.2@3108.44,379.73 ; v1(2999.51,615.95) U13.47@3053.98,615.95 ; C134.2@3108.45,381.5 3114.5,381.5 v1(3121,375)
  Top Layer L1 w16.5: v1(2471,947.84) 2471,932.66 C137.2@2477.66,926 C135.2@2525.28,926 2521,930.28 v1(2521,947.84) ; C133.2@2515.46,419.1 2515.46,404.7 v1(2521,399.16) ; C140.2@2515.46,468.32 2515.46,453.91 v1(2521,448.37) ; C142.2@2515.46,566.74 2515.46,581.14 v1(2521,586.68) ; C136.2@2671,808.01 v1(2671,829.07) ; C118.2@2782.72,215.03 v1(2803.77,215.03) ; v1(2871.3,801.51) C132.2@2871.3,781.24 C214.2@2927.6,781.24 v1(2927.6,801.51) ; C119.2@3010.46,210.03 v1(3031.52,210.03) ; C131.2@3124.45,571.41 v1(3124.45,592.47)
  Top Layer L1 w19.5: USB.5@330.71,719.44 v1(387.98,719.45)
  Top Layer L1 w24: v1(2427.74,603.08) R67.1@2456.47,603.08
  Bottom Layer - L10 w16.5: v1(275.94,670.86) 320.38,670.86 v1(329.24,662) ; v1@2999.51,616.47 2982.68,616.47 U15.5@2982.68,605.39 3037.17,605.39 C205.2@3048,594.56
  Bottom Layer - L10 w18: v1(2871.3,801.51) 2871.3,841.38 C212.1@2875.91,846
  Bottom Layer - L10 w24: C139.2@2514.19,477.1 2521,470.29 v1(2521,448.37) ; v1(2521,586.68) 2540.32,606 C141.2@2543.44,606
  other v1: 3134.5,251 2416.91,300.8 110.24,607.24 326.77,607.24 181.46,633.46 256.26,775.86 2899.45,781.24 3071,789.7 138.86,839 110.24,957.63 326.77,957.63
LMK04828_CSB: R68.1 R69.1 R98.1 R104.2 U6.18 | length 3392.3
  Top Layer L1 w8: U6.18@1296.79,2019.05 1341.95,2019.05 1521,1840 v1(1551,1840) ; R104.2@3398.44,398 R98.1@3398.44,440
  Top Layer L1 w18: R68.1@3351,440 R98.1@3398.44,440
  Signals - L3 w4: v1(1551,1840) 1564,1827 1564,1474 1607,1431 1688,1431 1854,1265 2137,1265 2219,1183 2219,1075 2284,1010 2703,1010 2798,915 v1(2865,915)
  Signals - L6 w4: v1(2865,915) 2993,915 3016,938 3276,938 3351,863 3351,616 3407,560 3407,529 3376.56,498.56 v1(3376.56,440)
  Bottom Layer - L10 w8: v1(3376.56,440) R69.1@3398.44,440
LMK04828_RESET: FMC_RX1.J16 R122.2 U6.5 | length 4841.4
  Top Layer L1 w9: v1(1054.66,1938.69) U6.5@1054.66,1973.77
  Signals - L6 w4: v1(1432,1890) 1457,1865 5381,1865 5394,1852 5394,1628 5381,1615 5294,1615 v3(5269,1590)
  Bottom Layer - L10 w8: v1(1054.66,1938.69) 1060.98,1945 1091,1945 1146,1890 v1(1432,1890) ; FMC_RX1.J16@5244,1565 v3(5269,1590)
  Bottom Layer - L10 w18: R122.2@1028.93,1938.69 v1(1054.66,1938.69)
LMK04828_SYNC: FMC_RX1.J15 R142.1 | length 4227.5
  Signals - L6 w4: v1(1432.55,1815) 5331,1815 5344,1802 5344,1678 5331,1665 5294,1665 v3(5269,1640)
  Bottom Layer - L10 w8: R142.1@1383.56,1843 1404.55,1843 v1(1432.55,1815) ; FMC_RX1.J15@5244,1615 v3(5269,1640)
LMK_TRF_CLK: R102.1 R115.1 R121.1 R129.2 U4.4 U6.19 | length 3794
  Top Layer L1 w8: U6.19@1296.79,2038.73 1367.27,2038.73 1466,1940 1736,1940 1847,2051 2331.08,2051 v1(2342.08,2040) U4.4@2342.08,1884.49 ; R102.1@3391.63,240 v1(3398.44,240) R115.1@3398.44,157.56
  Signals - L3 w4: v1(2342.08,2040) 2351.92,2030.16 2351.92,1737.08 2417,1672 2417,1527 2474,1470 2474,1419 2571,1322 2695,1322 3018.5,998.5 3121.5,998.5 v1(3276,844)
  Signals - L6 w4: v1(3276,844) 3276,560.44 3301,535.44 3301,337.44 v1(3398.44,240)
  Bottom Layer - L10 w8: v1(3398.44,240) R129.2@3398.44,282
LMK_TRF_DATA: R101.1 R114.1 R120.1 R128.2 U4.3 U6.20 | length 3686
  Top Layer L1 w8: U6.20@1296.79,2058.42 1447.42,2058.42 1479,2090 v1(2361.76,2090) U4.3@2361.76,1884.49 ; R114.1@3351,298 R128.2@3398.44,298 v1(3398.44,340)
  Signals - L3 w4: v1(2361.76,2090) 2391.29,2060.47 2391.29,1756.54 2513,1634.83 2513,1429 2581,1361 2747,1361 3050,1058 3112,1058 v1(3301,869)
  Signals - L6 w4: v1(3301,869) 3301,573 3326,548 3326,412.44 v1(3398.44,340)
LO1_N: C83.1 R34.2 U4.10 | length 266.8
  Top Layer L1 w8: C83.1@1997.73,1883.18 R34.2@2030.05,1883.18 2040.36,1893.5 2145.68,1893.5 2198.12,1841.05 2227.86,1841.05 2229.7,1839.21 U4.10@2237.75,1839.21
LO1_P: C75.1 R27.2 U4.9 | length 266.8
  Top Layer L1 w8: C75.1@1997.73,1919.81 R27.2@2030.05,1919.81 2040.36,1909.5 2152.3,1909.5 2204.75,1857.05 2227.86,1857.05 2229.7,1858.9 U4.9@2237.75,1858.9
LO2_N: LO2_N.1 U4.11 | length 166.2
  Top Layer L1 w8: LO2_N.1@2079.05,1833.99 2090.04,1823 2169.8,1823 2175.12,1817.68 2227.86,1817.68 2229.7,1819.53 U4.11@2237.75,1819.53
LO2_P: LO2_P.1 U4.12 | length 166.2
  Top Layer L1 w8: LO2_P.1@2079.05,1796.01 2090.04,1807 2163.18,1807 2168.49,1801.68 2227.86,1801.68 2229.7,1799.84 U4.12@2237.75,1799.84
LO3_N: LO3_N.1 U4.14 | length 153.6
  Top Layer L1 w8: LO3_N.1@2129.32,1728 2119,1738.31 2119,1754.63 2126.69,1762.31 2227.86,1762.31 2229.7,1760.47 U4.14@2237.75,1760.47
LO3_P: LO3_P.1 U4.13 | length 180.1
  Top Layer L1 w8: LO3_P.1@2092.69,1728 2103,1738.32 2103,1761.26 2120.06,1778.32 2227.86,1778.32 2229.7,1780.16 U4.13@2237.75,1780.16
LO4_N: C84.1 R35.2 U4.15 | length 267.8
  Top Layer L1 w8: C84.1@1996.73,1696.81 R35.2@2029.05,1696.81 2039.36,1686.5 2145.68,1686.5 2198.12,1738.95 2227.86,1738.95 2229.7,1740.79 U4.15@2237.75,1740.79
LO4_P: C76.1 R28.2 U4.16 | length 267.8
  Top Layer L1 w8: C76.1@1996.73,1660.18 R28.2@2029.05,1660.18 2039.36,1670.5 2152.3,1670.5 2204.75,1722.94 2227.86,1722.94 2229.7,1721.1 U4.16@2237.75,1721.1
NCO_0: NCO.1 R6.2 R7.1 R136.1 | length 502.4
  Top Layer L1 w8: v1(1583.2,1211.93) 1705.13,1090 NCO.1@1771.5,1090 1821.5,1140 R136.1@1821.5,1274.44
  Bottom Layer - L10 w8: R6.2@1771.5,1031.56 NCO.1@1771.5,1090
NCO_1: NCO.3 R5.2 R8.1 R137.1 | length 669.5
  Top Layer L1 w8: NCO.3@1871.5,1090 1921.5,1140 R137.1@1921.5,1276
  Bottom Layer - L10 w8: R8.1@1493.2,1152.88 1511.27,1134.81 1826.69,1134.81 NCO.3@1871.5,1090 R5.2@1871.5,1031.56
NCO_2: NCO.5 R4.2 R9.1 R138.1 | length 1227.9
  Top Layer L1 w8: v1(1251.86,1010.18) 1261.67,1020 1901.5,1020 NCO.5@1971.5,1090 ; R138.1@2390.94,1040 R4.2@2390.94,1090
  Bottom Layer - L10 w8: NCO.5@1971.5,1090 2012.5,1049 2367,1049 v1(2376,1040)
Net1V2ADC_INT_2: 1V2ADC_INT.2 C172.1 R83.2 U10.5 U10.6 U10.7 U10.8 | length 97.4
  Bottom Layer - L10 w51: 1V2ADC_INT.2@3330.26,2305 3337.35,2297.91 R83.2@3337.35,2210.56
Net1V2ADC_LDO_1: 1V2ADC_LDO.1 C185.1 C195.1 R84.1 R85.2 U10.1 U10.18 U10.19 U10.20 | length 97.4
  Bottom Layer - L10 w51: 1V2ADC_LDO.1@3023.27,2469 3030.35,2476.09 R84.1@3030.35,2563.44
  other v1: 3108.68,2445.56
Net1V2ADC_LDO_2: 1V2ADC_LDO.2 L15.1 L16.1 R84.2 | length 279.6
  Top Layer L1 w37: L15.1@2741,2469 L16.1@2829,2469 1V2ADC_LDO.2@2923.27,2469
  Bottom Layer - L10 w51: R84.2@2916.18,2563.44 2916.18,2476.09 1V2ADC_LDO.2@2923.27,2469
Net1V9ADC_1: 1V9ADC.1 C192.1 C198.1 C204.1 R92.1 R93.2 U11.4 | length 377.2
  Top Layer L1 w37: U11.4@4053.22,2502.93 1V9ADC.1@4285,2502.93
  Bottom Layer - L10 w24: v1(4149,2508.83) v1(4197,2508.83)
  Bottom Layer - L10 w51: 1V9ADC.1@4285,2502.93 4292.09,2495.84 R92.1@4379.44,2495.84
Net1V9ADC_2: 1V9ADC.2 L18.1 R92.2 | length 197.9
  Top Layer L1 w31.5: 1V9ADC.2@4285,2602.93 L18.1@4385.5,2602.93
  Bottom Layer - L10 w51: 1V9ADC.2@4285,2602.93 4292.09,2610.02 R92.2@4379.44,2610.02
Net1V9INT_2: 1V9INT.2 C196.1 R95.2 U11.1 U11.2 | length 487
  Top Layer L1 w37: U11.1@4053.22,2302.14 4168.07,2302.14 1V9INT.2@4234,2369.07 U11.2@4053.22,2369.07
  Bottom Layer - L10 w51: 1V9INT.2@4234,2369.07 4241.09,2376.16 R95.2@4328.44,2376.16
Net3P3USB_1: 3P3USB.1 C139.1 C140.1 L24.2 U13.9 | length 301.4
  Top Layer L1 w10: v1(2562.5,468.31) 2572.34,478.16 U13.9@2616.97,478.16
  Top Layer L1 w16.5: C140.1@2541.44,468.32 v1(2562.5,468.31)
  Bottom Layer - L10 w8: 3P3USB.1@2443,419 2503,419 2509,425 2532,425 2545,438 2545,450.81 v1(2562.5,468.31)
  Bottom Layer - L10 w24: v1(2562.5,468.31) 2585.18,491 L24.2@2627.5,491
Net5VDC_1: 5VDC.1 S1.2 | length 581.5
  Bottom Layer - L10 w50: 5VDC.1@539.37,235 930.2,235 S1.2@1065,100.2
Net5VDC_2: 5VDC.2 LF7.1 | length 1462.5
  Bottom Layer - L10 w50: 5VDC.2@303.15,235 329.15,261 415,261 529.51,375.51 1336.79,375.51 1454,258.31 1454,166.89 1381.6,94.49 LF7.1@1370.55,94.49
Net12V_1: 12V.1 R94.1 | length 88.2
  Top Layer L1 w25: R94.1@4746,342.15 4771,367.15 12V.1@4771,420
NetC1_2: C1.2 VIN+.1 | length 449.2
  Top Layer L1 w8: VIN+.1@580,963.32 580,1085.13 C1.2@811.52,1316.66
NetC2_1: C2.1 D2.1 R3.2 U1.3 | length 187.3
  Bottom Layer - L10 w8: D2.1@2681.95,1165 2761.02,1165 C2.1@2806.68,1210.67
  Bottom Layer - L10 w19.5: C2.1@2806.68,1210.67 R3.2@2806.69,1254.36
  other v1: 2812,1232.52
NetC3_2: C3.2 T1.6 | length 71.7
  Bottom Layer - L10 w8: T1.6@741.09,1304.17 795.1,1304.17 C3.2@807.59,1316.66
NetC4_1: C4.1 T1.2 | length 44.9
  Bottom Layer - L10 w8: C4.1@640.68,1330.16 T1.2@685.57,1330.16
NetC4_2: C4.2 VIN.1 | length 501.3
  Bottom Layer - L10 w8: VIN.1@100,1330.16 C4.2@601.31,1330.16
NetC5_2: C5.2 T1.4 | length 71.7
  Bottom Layer - L10 w8: T1.4@741.09,1356.14 795.1,1356.14 C5.2@807.59,1343.66
NetC6_1: C6.1 VIN-.1 | length 449.2
  Top Layer L1 w8: VIN-.1@580,1697 580,1575.18 C6.1@811.52,1343.66
NetC7_2: C7.2 U2.33 | length 139.9
  Bottom Layer - L10 w8: U2.33@1301.18,1532.91 1299.34,1534.76 1299.34,1664.32 C7.2@1304.84,1669.81
NetC8_1: C8.1 D4.1 R11.2 U1.5 | length 222.2
  Top Layer L1 w8: D4.1@2681.95,1115 2701.95,1095 2743,1095 2762,1076 U1.5@2762,1047.48 C8.1@2762,985 R11.2@2762,950
NetC9_2: C9.2 U2.32 | length 139.9
  Bottom Layer - L10 w8: C9.2@1277.84,1669.81 1283.34,1664.31 1283.34,1534.76 U2.32@1281.5,1532.91
NetC10_2: C10.2 U2.36 | length 229.9
  Bottom Layer - L10 w8: U2.36@1356.3,1477.8 1358.14,1479.64 1577.7,1479.64 C10.2@1583.2,1474.14
NetC11_1: C11.1 R1.1 R12.2 U1.2 U1.6 | length 281.1
  Top Layer L1 w19.5: U1.6@2812,1047.48 2812,1115 v1(2837,1140) 2862,1165 U1.2@2862,1232.52
  Bottom Layer - L10 w19.5: R12.2@2837,1122 C11.1@2837,1158 ; v1(2837,1140) R1.1@2876.32,1140
NetC12_2: C12.2 U2.35 | length 229.9
  Bottom Layer - L10 w8: U2.35@1356.3,1497.48 1358.14,1495.64 1577.7,1495.64 C12.2@1583.2,1501.14
NetC13_2: C13.2 U2.39 | length 139.9
  Bottom Layer - L10 w8: U2.39@1356.3,1418.74 1358.14,1420.58 1487.7,1420.58 C13.2@1493.2,1415.08
NetC14_2: C14.2 U2.38 | length 139.9
  Bottom Layer - L10 w8: U2.38@1356.3,1438.43 1358.14,1436.58 1487.7,1436.58 C14.2@1493.2,1442.08
NetC15_2: C15.2 U2.42 | length 229.9
  Bottom Layer - L10 w8: U2.42@1356.3,1359.68 1358.14,1361.53 1577.7,1361.53 C15.2@1583.2,1356.03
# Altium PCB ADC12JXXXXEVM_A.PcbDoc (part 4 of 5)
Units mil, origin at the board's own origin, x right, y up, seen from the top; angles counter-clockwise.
Board outline 5739 x 2680 mil, 10 copper layers (Top Layer L1, Gnd-Plane - L2, Signals - L3, Gnd-Plane - L4, Pwr Plane - L5, Signals - L6, Gnd-Plane - L7, Signals - L8, Gnd-Plane - L9, Bottom Layer - L10), stack 57.8 mil thick; 582 components, 343 nets, 1924 pads, 1319 vias.

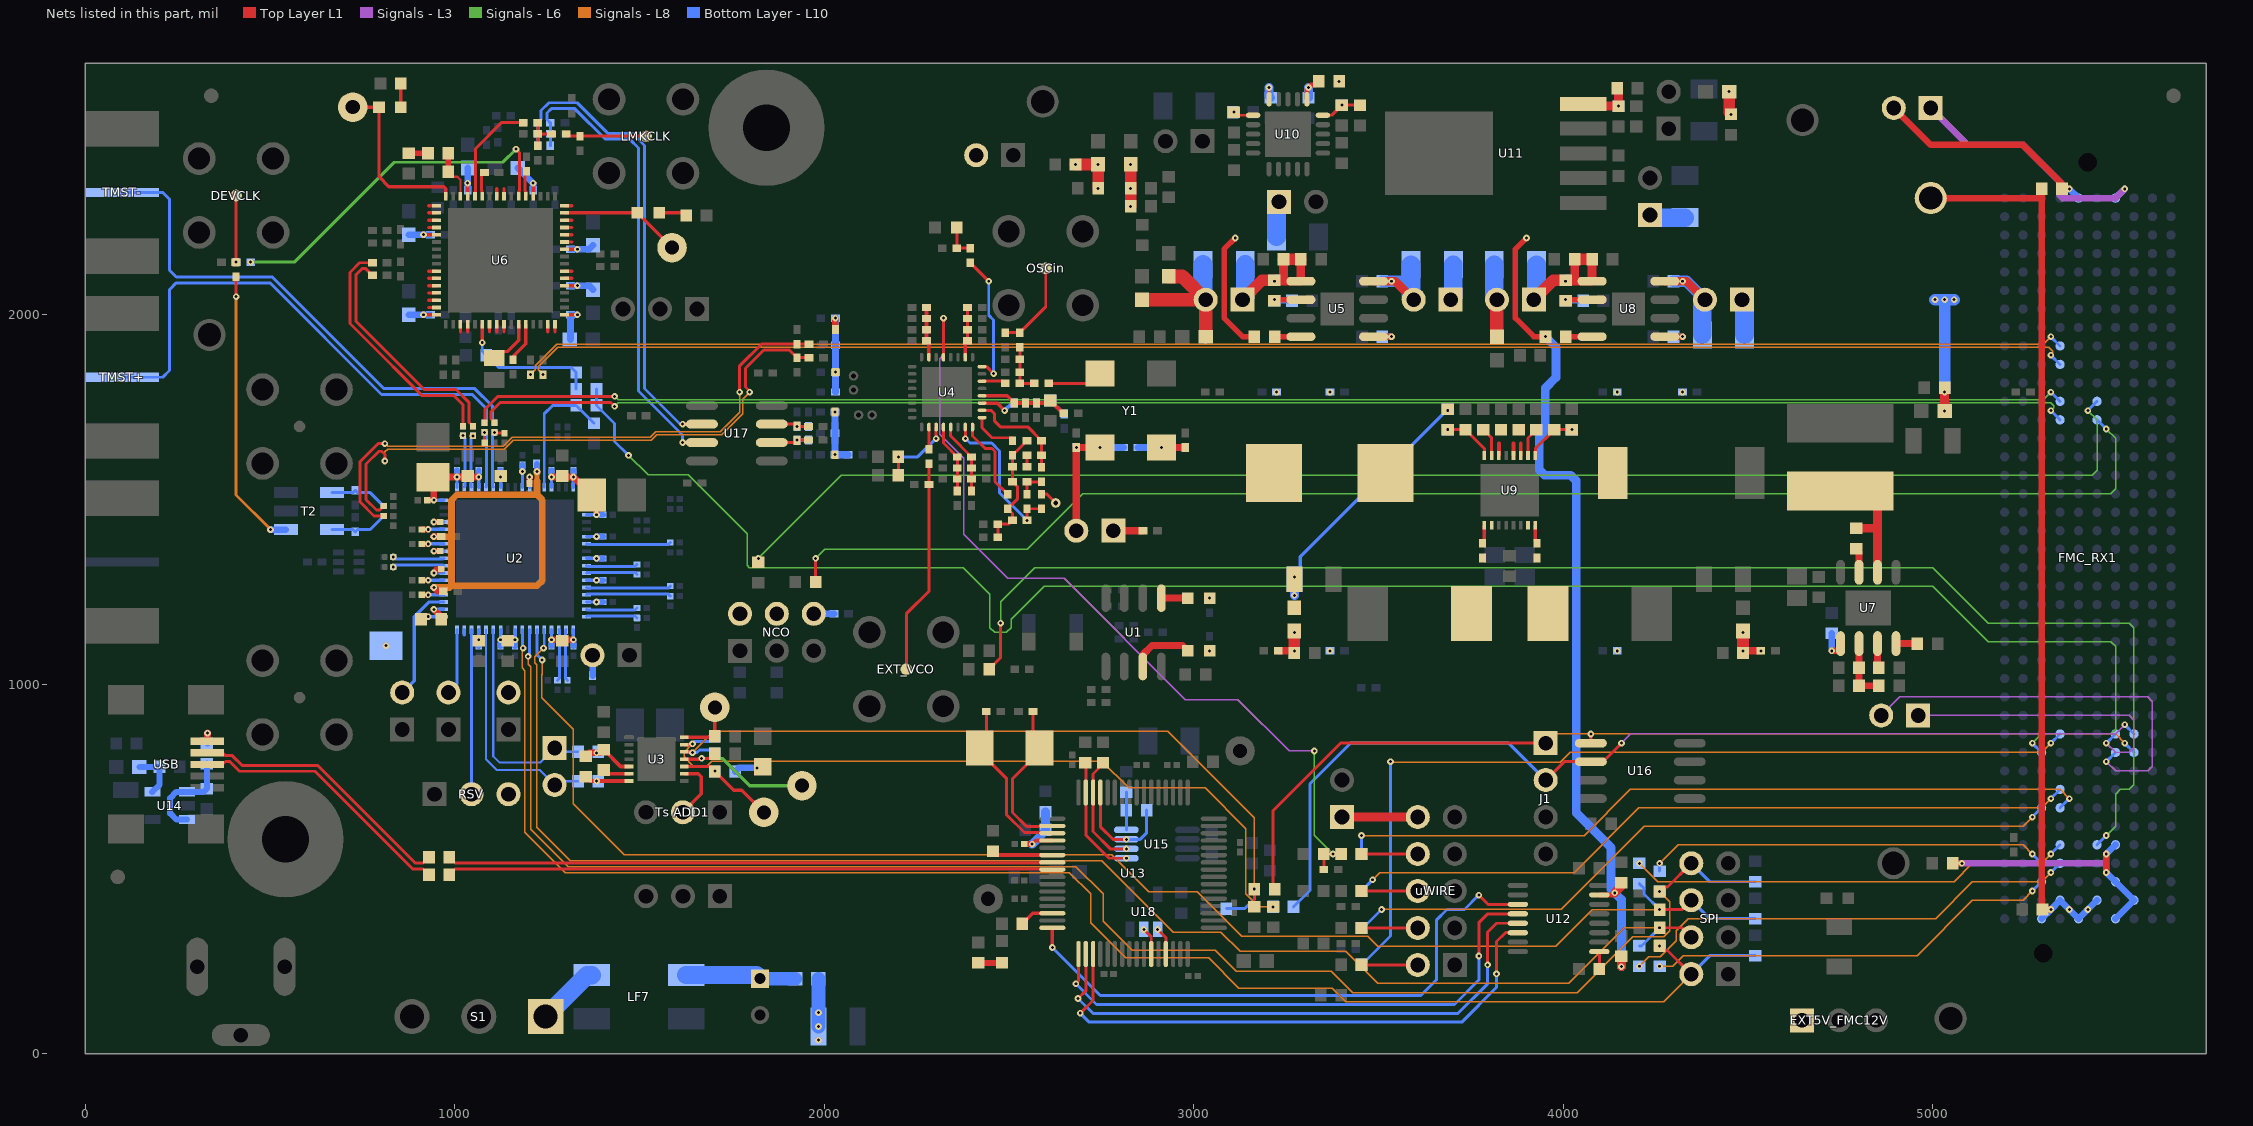
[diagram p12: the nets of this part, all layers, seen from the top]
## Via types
v1: diameter 18, hole 8, Top Layer L1 to Bottom Layer - L10, tented both sides, 1099 vias
v2: diameter 19.68, hole 7.87, Top Layer L1 to Bottom Layer - L10, 99 vias
v3: diameter 18, hole 8, Top Layer L1 to Bottom Layer - L10, tented bottom, 58 vias
v4: diameter 18, hole 8, Top Layer L1 to Bottom Layer - L10, tented top, 48 vias
v5: diameter 25.98, hole 12.99, Top Layer L1 to Bottom Layer - L10, tented top, 8 vias
v6: diameter 19.68, hole 7.87, Top Layer L1 to Bottom Layer - L10, tented top, 5 vias
v7: diameter 126, hole 106, Top Layer L1 to Bottom Layer - L10, tented top, 2 vias

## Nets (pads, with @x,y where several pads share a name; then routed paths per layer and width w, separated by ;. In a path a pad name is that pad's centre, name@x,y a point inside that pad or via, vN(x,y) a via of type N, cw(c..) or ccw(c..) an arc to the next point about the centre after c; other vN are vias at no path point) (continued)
NetC16_2: C16.2 C18.2 C19.2 U2.5 U2.12 U2.29 | length 1287.4
  Top Layer L1 w18: v1(943.26,1261.26) 953.31,1251.21 C18.2@968.57,1251.2 ; v1(943.26,1399.05) C19.2@963.52,1399.05
  Signals - L8 w13: 1222.44,1549.33 v1@1222.44,1570.92
  Signals - L8 w18: v1(943.26,1261.26) 986.22,1261.26 991.14,1266.18 ; v1(943.26,1399.05) 991.14,1399.05 ; 990.79,1497.48 1005.56,1512.24 1222.79,1512.24 ; 991.14,1497.83 991.14,1266.18 ; 1222.44,1549.33 1222.44,1512.59 1237.2,1497.83 1237.2,1280.6 1222.79,1266.18 991.14,1266.18 ; v1@1222.44,1570.92 v1(1222.44,1575.13)
  Bottom Layer - L10 w9: v1(943.26,1261.26) U2.5@970.47,1261.26 ; v1(943.26,1399.05) U2.12@970.47,1399.06 ; U2.29@1222.44,1532.91 v1(1222.44,1575.13)
  Bottom Layer - L10 w16: v1(1222.44,1575.13) C16.2@1222.44,1595.94
NetC17_2: C17.2 U2.41 | length 229.9
  Bottom Layer - L10 w8: U2.41@1356.3,1379.37 1358.14,1377.53 1577.7,1377.53 C17.2@1583.2,1383.03
NetC20_2: C20.2 U2.45 | length 139.9
  Bottom Layer - L10 w8: U2.45@1356.3,1300.63 1358.14,1302.47 1487.7,1302.47 C20.2@1493.2,1296.97
NetC21_2: C21.2 U2.44 | length 139.9
  Bottom Layer - L10 w8: U2.44@1356.3,1320.31 1358.14,1318.47 1487.7,1318.47 C21.2@1493.2,1323.97
NetC22_2: C22.2 R7.2 U2.48 | length 229.9
  Bottom Layer - L10 w8: U2.48@1356.3,1241.57 1358.14,1243.42 1577.7,1243.42 C22.2@1583.2,1237.92
NetC23_2: C23.2 U2.47 | length 229.9
  Bottom Layer - L10 w8: U2.47@1356.3,1261.26 1358.14,1259.42 1577.7,1259.42 C23.2@1583.2,1264.92
NetC26_2: C26.2 R8.2 U2.51 | length 139.9
  Bottom Layer - L10 w8: U2.51@1356.3,1182.52 1358.14,1184.36 1487.7,1184.36 C26.2@1493.2,1178.86
NetC28_2: C28.2 U2.50 | length 139.9
  Bottom Layer - L10 w8: U2.50@1356.3,1202.2 1358.14,1200.36 1487.7,1200.36 C28.2@1493.2,1205.86
NetC29_2: C29.2 R9.2 U2.54 | length 139.9
  Bottom Layer - L10 w8: C29.2@1277.84,1010.19 1283.34,1015.68 1283.34,1145.24 U2.54@1281.5,1147.09
NetC30_2: C30.2 C229.1 T2.4 | length 159.6
  Bottom Layer - L10 w8: T2.4@668.25,1417.95 724.67,1417.95 C229.1@730.85,1411.77 737.03,1417.95 771.09,1417.95 C30.2@807.59,1454.45
NetC31_2: C31.2 U2.53 | length 139.9
  Bottom Layer - L10 w8: U2.53@1301.18,1147.09 1299.34,1145.24 1299.34,1015.69 C31.2@1304.84,1010.19
NetC34_1: C34.1 U3.6 | length 72.4
  Top Layer L1 w10: C34.1@1403.28,767.44 1413.33,757.39 U3.6@1471.47,757.39
NetC34_2: C34.2 C38.2 R100.2 U3.5 | length 143.5
  Top Layer L1 w10: C34.2@1403.28,822.56 1448.76,777.07 U3.5@1471.47,777.07
  Top Layer L1 w18: C38.2@1354.28,804.56 1363.72,814 1394.72,814 C34.2@1403.28,822.56
  other v1: 1383.78,814
NetC36_2: C36.2 C228.1 T2.6 | length 159.6
  Bottom Layer - L10 w8: T2.6@668.25,1517.95 724.67,1517.95 C228.1@730.85,1524.14 737.03,1517.95 771.09,1517.95 C36.2@807.59,1481.45
NetC38_1: C38.1 R99.2 U3.7 | length 122.1
  Top Layer L1 w10: C38.1@1354.28,749.44 1366.02,737.7 U3.7@1471.47,737.7
  other v1: 1383.78,737.7
NetC73_2: C73.2 C74.2 J2.2 R133.2 Y1.4 | length 352.6
  Top Layer L1 w19.68: J2.2@2682,1415 v1(2682,1640) v1(2746.56,1640)
  Bottom Layer - L10 w18: v1(2746.56,1640) R133.2@2809.55,1640
NetC76_2: C76.2 R33.2 R162.2 R163.1 U17.2 | length 134.6
  Top Layer L1 w8: U17.2@1857.82,1653.5 1919.36,1653.5 v1(1926.05,1660.18) C76.2@1957.36,1660.18 C76.2@1958.36,1660.18
  Bottom Layer - L10 w8: v1(1926.05,1660.18) R163.1@1957.36,1660.18
NetC77_1: C77.1 C78.1 C81.1 L1.2 R27.1 R34.1 | length 230.8
  Top Layer L1 w18: R27.1@2030.05,1959.18 v1(2030.05,1990)
  Bottom Layer - L10 w19.68: L1.2@2030.05,1790 v1(2030.05,1843.81) v1(2030.05,1990)
NetC79_1: C79.1 C80.1 C82.1 L34.2 R28.1 R35.1 | length 149.6
  Bottom Layer - L10 w19.68: v1(2029.05,1736.18) v1(2029.05,1620.81) L34.2@2063.32,1620.82
NetC84_2: C84.2 R37.2 R162.1 R164.1 U17.3 | length 126.1
  Top Layer L1 w8: U17.3@1857.82,1703.5 R162.1@1919.36,1703.5 ; R162.1@1925.36,1697.5 v1(1926.05,1696.81) C84.2@1957.36,1696.81 C84.2@1958.36,1696.81
  Bottom Layer - L10 w8: v1(1926.05,1696.81) R164.1@1957.36,1696.82
NetC85_2: C85.2 U6.43 | length 67.8
  Top Layer L1 w8: U6.43@1074.35,2320.23 1074.35,2332.23 1072.5,2334.07 1072.5,2376.19 C85.2@1080.31,2384
NetC86_1: C86.1 C123.2 R48.1 R50.1 | length 99.6
  Top Layer L1 w8: C123.2@1224.67,2456.69 R50.1@1224.67,2489 ; C86.1@1224.67,2519 R50.1@1224.67,2489 ; R48.1@1261.98,2489 R50.1@1224.67,2489
NetC86_2: C86.2 U6.44 | length 287.6
  Top Layer L1 w8: U6.44@1054.66,2320.23 1054.66,2332.23 1056.5,2334.07 1056.5,2449.5 1126,2519 C86.2@1185.3,2519
NetC87_1: C87.1 U6.38 | length 976.4
  Top Layer L1 w8: v1(1165.61,2447.5) 1174.61,2438.5 1174.61,2334.07 1172.77,2332.23 U6.38@1172.77,2320.23
  Signals - L6 w8: v1(447.68,2141.68) 565.68,2141.68 836,2412 1130.12,2412 v1(1165.61,2447.5)
NetC87_2: C87.2 C89.1 DEVCLK.1 R165.2 | length 180.3
  Top Layer L1 w8: v1(408.31,2141.68) DEVCLK.1@408.31,2322
NetC88_1: C88.1 U6.37 | length 69.3
  Top Layer L1 w8: U6.37@1192.46,2320.23 1192.46,2332.23 1190.61,2334.07 1190.61,2383.93 C88.1@1194,2387.32
NetC89_2: C89.2 T2.3 | length 764.7
  Top Layer L1 w8: v1(408.31,2048.5) C89.2@408.31,2102.31
  Signals - L8 w8: v1(408.31,2048.5) 408.31,1511.64 v1@502,1417.95
  Bottom Layer - L10 w18: v1(501.57,1417.95) T2.3@543.06,1417.95
NetC117_1: C117.1 C126.1 C166.1 LMK_LDO.1 R40.1 R41.2 U5.5 | length 443.2
  Top Layer L1 w23.5: C117.1@3218,2092.56 3220.56,2090 U5.5@3289.57,2090 C126.1@3289.57,2150 ; 3242.56,2090 C166.1@3242.56,2150
  Top Layer L1 w31.5: LMK_LDO.1@3132,2040 3184.56,2092.56 C117.1@3215.44,2092.56 ; C166.1@3242.56,2150 C126.1@3289.57,2150
  Bottom Layer - L10 w51: LMK_LDO.1@3132,2040 3139.09,2047.09 R40.1@3139.09,2135.44
  other v1: 3218,2090
NetC117_2: C117.2 R41.1 R49.2 U5.6 | length 120.1
  Top Layer L1 w15: C117.2@3218,2037.44 3220.56,2040 U5.6@3289.57,2040
  Bottom Layer - L10 w15: R41.1@3218,2037.44 R49.2@3265.44,2037.44
  other v1: 3218,2040
NetC122_1: C122.1 U6.11 | length 129.3
  Top Layer L1 w9: C122.1@1106.9,1882.27 1124.37,1899.74 1142.3,1899.74 1172.77,1930.21 U6.11@1172.77,1973.77
NetC124_1: C124.1 U6.12 | length 110.9
  Top Layer L1 w9: C124.1@1157.3,1877.43 1157.3,1885.74 1192.46,1920.9 U6.12@1192.46,1973.77
NetC127_1: C127.1 LMK_INT.2 R42.2 U5.4 | length 304.5
  Top Layer L1 w23.5: U5.4@3486.43,2090 v1(3534.79,2090) 3545,2090 LMK_INT.2@3595,2040
  Bottom Layer - L10 w31.5: C127.1@3510.05,2090 v1(3534.79,2090) 3587.91,2090
  Bottom Layer - L10 w51: R42.2@3587.91,2134.44 3587.91,2047.09 LMK_INT.2@3595,2040
NetC128_1: C128.1 U5.1 | length 73.1
  Top Layer L1 w18: U5.1@3486.43,1940 v1(3534.8,1940)
  Bottom Layer - L10 w18: C128.1@3510.05,1940 v1(3534.8,1940)
NetC135_1: C135.1 U13.2 Y2.1 | length 435
  Top Layer L1 w8: C135.1@2564.65,926 2564.65,844.53 Y2.1@2582.18,827 2582.18,816.71 2509.47,744 2509.47,652.63 2547.99,614.11 2582.63,614.11 2584.47,615.95 U13.2@2616.97,615.95
NetC137_1: C137.1 U13.3 Y2.2 | length 461.5
  Top Layer L1 w8: C137.1@2438.29,926 2438.29,844.53 Y2.2@2420.76,827 2420.76,816.71 2493.47,744 2493.47,646 2541.36,598.11 2582.63,598.11 2584.47,596.27 U13.3@2616.97,596.27
NetC141_1: C141.1 C142.1 L25.2 U13.4 | length 182.2
  Top Layer L1 w10: v1(2562.5,566.74) 2572.34,576.58 U13.4@2616.97,576.58
  Top Layer L1 w16.5: C142.1@2541.44,566.74 v1(2562.5,566.74)
  Bottom Layer - L10 w24: v1(2562.5,566.74) 2598.56,602.8 C141.1@2598.56,606 L25.2@2598.56,654.44
NetC148_1: C148.1 L8.1 U7.6 | length 378.7
  Top Layer L1 w23.62: L8.1@4749,1522.46 4850,1522.46 U7.6@4850,1302.46 ; C148.1@4792.27,1421.56 4850,1421.56
NetC148_2: C148.2 U7.7 | length 67.2
  Top Layer L1 w18: C148.2@4792.27,1366.44 4800,1358.71 U7.7@4800,1302.46
NetC149_1: C149.1 C150.1 C151.1 LMX_LDO.1 R73.1 R74.2 U8.5 | length 442.2
  Top Layer L1 w23.5: C149.1@4006,2092.56 4008.56,2090 U8.5@4077.57,2090 C151.1@4077.57,2150 ; 4030.56,2090 C150.1@4030.56,2150
  Top Layer L1 w31.5: LMX_LDO.1@3920,2040 3972.56,2092.56 C149.1@4003.44,2092.56 ; C150.1@4030.56,2150 C151.1@4077.57,2150
  Bottom Layer - L10 w51: LMX_LDO.1@3920,2040 3927.09,2047.09 R73.1@3927.09,2134.44
  other v1: 4006,2090
NetC149_2: C149.2 R74.1 R77.2 U8.6 | length 120.1
  Top Layer L1 w15: C149.2@4006,2037.44 4008.56,2040 U8.6@4077.57,2040
  Bottom Layer - L10 w15: R74.1@4006,2037.44 R77.2@4053.44,2037.44
  other v1: 4006,2040
NetC154_1: C154.1 R72.2 R76.2 U7.2 | length 168
  Top Layer L1 w18: U7.2@4800,1109.54 R72.2@4800,995 R76.2@4853.44,995
NetC155_1: C155.1 U7.3 | length 65.5
  Top Layer L1 w18: C155.1@4850,1044 U7.3@4850,1109.54
NetC158_1: C158.1 C159.1 L7.2 LMK_INT.1 LMX_INT.1 R42.1 R75.1 | length 610.3
  Top Layer L1 w24: v1(5031.5,1739.21) C159.1@5031.5,1802
  Bottom Layer - L10 w24: v1(5031.5,1739.21) C158.1@5031.5,1802
  Bottom Layer - L10 w31.5: v1(5005.5,2040) v1(5057.5,2040) ; C158.1@5031.5,1802 v1(5031.5,2040)
  Bottom Layer - L10 w51: LMK_INT.1@3695,2040 3702.09,2047.09 R42.1@3702.09,2134.44 ; LMX_INT.1@4483,2040 4490.09,2032.91 R75.1@4490.09,1945.56
  other v1: 5031.5,1790
NetC160_1: C160.1 LMX_INT.2 R75.2 U8.4 | length 332.3
  Top Layer L1 w23.5: U8.4@4274.43,2090 v1(4322.79,2090) 4333,2090 LMX_INT.2@4383,2040
  Bottom Layer - L10 w31.5: C160.1@4298.05,2090 v1(4322.79,2090) 4333,2090 LMX_INT.2@4383,2040
  Bottom Layer - L10 w51: R75.2@4375.91,1945.56 4375.91,2032.91 LMX_INT.2@4383,2040
NetC161_1: C161.1 U8.1 | length 73.1
  Top Layer L1 w18: U8.1@4274.43,1940 v1(4322.8,1940)
  Bottom Layer - L10 w18: C161.1@4298.05,1940 v1(4322.8,1940)
NetC162_1: C162.1 U7.4 | length 57.4
  Top Layer L1 w18: U7.4@4900,1109.54 C162.1@4957.44,1109.54
NetC168_1: C168.1 R78.2 U9.3 U9.4 U9.6 | length 100.5
  Top Layer L1 w10: U9.6@3825.47,1618.49 3825.47,1652 ; U9.4@3864.84,1618.49 3864.84,1652 ; U9.3@3884.53,1618.49 3884.53,1652
NetC169_1: C169.1 U9.16 | length 50.8
  Top Layer L1 w10: U9.16@3923.9,1429.51 3923.9,1385.53 C169.1@3928.74,1380.68
NetC169_2: C169.2 D11.1 L11.2 U9.15
NetC170_1: C170.1 D12.1 L12.1 U9.10
NetC170_2: C170.2 U9.9 | length 50.8
  Top Layer L1 w10: C170.2@3781.26,1380.69 3786.1,1385.53 U9.9@3786.1,1429.51
NetC174_1: C174.1 R81.2 R86.2 U9.1 | length 139.1
  Top Layer L1 w8: U9.1@3923.9,1618.49 3923.9,1637.34 R86.2@3975,1688.44 v1(4023,1688.44)
NetC175_2: C175.2 R82.1 R87.2 U9.8 | length 139.1
  Top Layer L1 w8: v1(3687,1688.44) R87.2@3735,1688.44 3786.1,1637.34 U9.8@3786.1,1618.49
NetC178_1: C178.1 U9.2 | length 79.4
  Top Layer L1 w8: U9.2@3904.21,1618.49 3904.21,1665.65 C178.1@3927,1688.44
NetC179_1: C179.1 U9.7 | length 79.4
  Top Layer L1 w8: C179.1@3783,1688.44 3805.79,1665.65 U9.7@3805.79,1618.49
NetC186_1: C186.1 R79.1 R90.2 U10.10 | length 111.9
  Top Layer L1 w8: U10.10@3349.16,2539.18 3373.3,2539.18 v1(3400.68,2566.56) R79.1@3449.68,2566.56
NetC187_1: C187.1 U10.15 | length 61.2
  Top Layer L1 w8: U10.15@3203.49,2582.49 v1(3203.49,2614.17)
  Bottom Layer - L10 w24: v1(3203.49,2614.17) 3203.49,2590.61 C187.1@3207.67,2586.43
NetC192_2: C192.2 R93.1 R96.2 U11.5 | length 147.7
  Top Layer L1 w24: U11.5@4053.22,2569.86 4059.13,2563.95 v1(4149,2563.95) 4149,2608.44 R96.2@4145.44,2612
NetC193_1: C193.1 L17.1 LF7.3 | length 298.8
  Bottom Layer - L10 w37: C193.1@1826,202.76 L17.1@1921.16,202.76
  Bottom Layer - L10 w49: LF7.3@1626.46,212.6 1816.16,212.6 C193.1@1826,202.76
NetC194_1: C194.1 EXT5V_FMC12V.1 L17.2 | length 129.3
  Bottom Layer - L10 w37: C194.1@1984.15,73.49 L17.2@1984.15,202.76
  other v1: 1984.15,36.28 1984.15,73.49 1984.15,110.7
NetC201_1: C201.1 R103.2 U14.1 U14.3 | length 271.6
  Bottom Layer - L10 w16.5: U14.3@275.94,633.46 246.64,633.46 229.76,650.33 229.76,691.39 246.64,708.26 U14.1@275.94,708.26 320.38,708.26 C201.1@329.24,717.12 R103.2@329.24,784.4
NetC211_1: C211.1 L26.1 U14.5 | length 130.2
  Bottom Layer - L10 w16.5: L26.1@146.73,775.86 C211.1@201.14,775.86 201.14,727.95 U14.5@181.46,708.26
NetC230_1: C230.1 C231.2 C232.1 C233.1 L27.2 U4.27 | length 256.3
  Top Layer L1 w9.45: U4.27@2426.72,1760.47 2467.69,1760.47 v1(2488.17,1740)
  Bottom Layer - L10 w11.02: v1(2488.17,1740) 2508.64,1760.47 C233.1@2514.33,1760.47 C232.1@2544.33,1760.47 C231.2@2574.33,1760.47 2604.46,1760.47 C230.1@2611.33,1767.35 L27.2@2648,1730.68
NetC234_1: C234.1 C235.2 C236.1 C237.1 L28.2 U4.28 | length 244
  Top Layer L1 w9.45: U4.28@2426.72,1780.16 2494.65,1780.16 C237.1@2514.33,1760.47
  Top Layer L1 w11.02: C237.1@2514.33,1760.47 C236.1@2544.33,1760.47 C235.2@2574.33,1760.47 2604.46,1760.47 C234.1@2611.33,1767.35 L28.2@2645.55,1733.13
NetC238_1: C238.1 C239.1 C240.1 L29.2 U4.21 | length 196.5
  Top Layer L1 w8: U4.21@2342.08,1695.51 2342.08,1671.16 C238.1@2398.55,1614.68 C239.1@2398.55,1584.68 C240.1@2398.55,1554.68 L29.2@2398.55,1522.37
NetC241_1: C241.1 C242.1 C243.1 L30.2 U4.20 | length 188.7
  Top Layer L1 w8: U4.20@2322.39,1695.51 2322.39,1652.21 C241.1@2359.92,1614.68 C242.1@2359.92,1584.68 C243.1@2359.92,1554.68 L30.2@2359.92,1522.37
NetC244_1: C244.1 C245.1 R91.1 U4.26 | length 278.6
  Top Layer L1 w8: U4.26@2426.72,1740.79 2451.08,1740.79 2461.14,1730.72 2461.14,1711.28 2476.33,1696.09 2550.57,1696.09 C245.1@2587.98,1658.68 C244.1@2587.98,1619.31 R91.1@2587.98,1586.68
NetC244_2: C244.2 R144.2 | length 31.3
  Top Layer L1 w8: R144.2@2548.61,1588 C244.2@2548.61,1619.31
NetC245_2: C245.2 C246.2 C247.2 R144.1 R145.2 R146.2 R147.1 R149.1 | length 332.4
  Top Layer L1 w8: R147.1@2469.68,1397.5 R146.2@2469.68,1432.5 2498.74,1432.5 C247.2@2509.24,1443 2509.24,1461.31 R149.1@2496.24,1474.31 2522.24,1500.31 2522.24,1534.31 C246.2@2509.24,1547.31 R144.1@2509.24,1588 R145.2@2509.24,1619.31 C245.2@2548.61,1658.68
NetC246_1: C246.1 R91.2 R148.1 | length 73
  Top Layer L1 w8: R148.1@2548.61,1513.68 C246.1@2548.61,1547.31 R91.2@2587.98,1547.31
NetC247_1: C247.1 R148.2 R150.1 U4.23 | length 426.8
  Top Layer L1 w8: v1@2381.45,1664.93 U4.23@2381.45,1695.51 ; v1(2548.61,1443) R148.2@2548.61,1474.31 R150.1@2587.98,1474.31
  Bottom Layer - L10 w8: v1@2381.45,1664.93 2394.38,1652 2453,1652 2474,1631 2474,1517.61 v1(2548.61,1443)
  other v1: 2381.45,1664.07
NetC248_1: C248.1 U4.18 | length 59.8
  Top Layer L1 w8: C248.1@2283.02,1635.68 U4.18@2283.02,1695.51
NetC248_2: C248.2 EXT_VCO.1 R153.2 | length 581.6
  Top Layer L1 w8: EXT_VCO.1@2222.02,1040 2222.02,1190.02 2283.02,1251.02 R153.2@2283.02,1540 C248.2@2283.02,1596.31
NetC249_1: C249.1 U4.30 | length 65.3
  Top Layer L1 w8: U4.30@2426.72,1819.53 2483.8,1819.53 C249.1@2489.65,1813.69
NetC249_2: C249.2 C251.2 R24.2 R25.2 R38.1 | length 137
  Top Layer L1 w8: R25.2@2529.02,1911.41 C249.2@2529.02,1813.69 R38.1@2568.32,1813.68
NetC250_2: C250.2 LD.1 R154.1 | length 92.3
  Top Layer L1 w8: LD.1@2358.69,2235.37 C250.2@2358.68,2179.37 R154.1@2395,2179.37
NetC252_1: C252.1 C253.1 C254.1 L32.2 U4.2 | length 137.2
  Top Layer L1 w8: C254.1@2387.75,1929.09 L32.2@2387.75,2019.09
  Top Layer L1 w9.45: U4.2@2381.45,1884.49 2381.45,1922.8 C254.1@2387.75,1929.09
NetC255_1: C255.1 C256.1 C257.1 L33.2 U4.7 | length 137.2
  Top Layer L1 w9.45: C257.1@2276.72,1929.09 2283.02,1922.8 U4.7@2283.02,1884.49
  Top Layer L1 w11.02: C257.1@2276.72,1929.09 C256.1@2276.72,1959.09 C255.1@2276.72,1989.09 L33.2@2276.72,2019.09
NetFMC_RX1_C30: FMC_RX1.C30 J1.2 R127.2 U16.6 | length 2740.7
  Top Layer L1 w8: J1.2@3952,740 4002,790 U16.6@4074.14,790 4107.2,790 v1(4157.2,840)
  Signals - L3 w4: v1(4157.2,840) 4182.2,865 5494,865 v3(5519,890)
  Bottom Layer - L10 w8: R127.2@3269.68,397.13 3314,441.45 3314,730 3424,840 3852,840 J1.2@3952,740 ; v3(5519,890) FMC_RX1.C30@5544,865
NetFMC_RX1_C31: FMC_RX1.C31 J1.1 R126.2 U16.5 | length 2673.6
  Top Layer L1 w8: R126.2@3214.56,445 3214.56,657.56 3397,840 J1.1@3952,840 ; U16.5@4074.14,840 v1(4074.14,865)
  Signals - L8 w4: J1.1@3952,840 3977,865 5494,865 v3(5519,840)
  Bottom Layer - L10 w8: v3(5519,840) FMC_RX1.C31@5544,815
NetFMC_RX1_C39: FMC_RX1.C39 FMC_RX1.D36 FMC_RX1.D38 FMC_RX1.D40 R132.2 | length 727.6
  Top Layer L1 w18: R132.2@5053.56,515 v1(5078.31,515) ; v1(5469,490) v1(5469,540)
  Signals - L3 w18: v1(5078.31,515) 5469,515 ; v1(5469,490) v1(5469,540)
  Bottom Layer - L10 w18: v1(5469,490) FMC_RX1.D38@5494,465 FMC_RX1.C39@5544,415 FMC_RX1.D40@5494,365 ; v1(5469,540) FMC_RX1.D36@5494,565
NetFMC_RX1_D30: "KC705 JTAG.1" FMC_RX1.D30 | length 789.5
  Signals - L3 w4: 4960,915 5531,915 5544,902 5544,828 5531,815 5494,815 v3(5469,840)
  Bottom Layer - L10 w8: v3(5469,840) FMC_RX1.D30@5494,865
NetFMC_RX1_D31: "KC705 JTAG.2" FMC_RX1.D31 | length 1110.2
  Signals - L3 w4: 4860,915 4910,965 5581,965 5594,952 5594,778 5581,765 5494,765 v3(5469,790)
  Bottom Layer - L10 w8: v3(5469,790) FMC_RX1.D31@5494,815
NetFMC_RX1_E12: FMC_RX1.E12 R136.2 | length 3928.8
  Signals - L6 w4: v1(1821.5,1340) 2046.5,1565 5431,1565 5444,1578 5444,1715 v3(5419,1740)
  Bottom Layer - L10 w8: v3(5419,1740) FMC_RX1.E12@5444,1765
NetFMC_RX1_E13: FMC_RX1.E13 R137.2 | length 3867
  Top Layer L1 w8: R137.2@1976.62,1276 v1(1976.62,1340)
  Signals - L6 w4: v1(1976.62,1340) 2001.62,1365 2549,1365 2699,1515 5481,1515 5494,1528 5494,1665 v3(5469,1690)
  Bottom Layer - L10 w8: FMC_RX1.E13@5444,1715 v3(5469,1690)
NetFMC_RX1_E36: FMC_RX1.E36 R138.2 | length 4010.9
  Top Layer L1 w8: R138.2@2446.06,1040 2477,1070.94 v1(2477,1165)
  Signals - L6 w4: v1(2477,1165) 2477,1223 2569,1315 4999,1315 5149,1165 5531,1165 5544,1152 5544,728 5531,715 5507,715 5494,702 5494,615 v3(5469,590)
  Bottom Layer - L10 w8: FMC_RX1.E36@5444,565 v3(5469,590)
NetFMC_RX1_G30: FMC_RX1.G30 R121.2 | length 2425
  Signals - L8 w4: v1@3532.99,789.01 3992.01,789.01 4018,815 5294,815 v3(5319,840)
  Bottom Layer - L10 w8: R121.2@3453.56,240 3532,318.44 v1(3532,790) ; v3(5319,840) FMC_RX1.G30@5344,865
NetFMC_RX1_G33: FMC_RX1.G33 R69.2 | length 2004.3
  Signals - L8 w4: v1(3484,470.44) 3503.56,490 4029,490 4204,665 5294,665 v3(5319,690)
  Bottom Layer - L10 w8: R69.2@3453.56,440 v1(3484,470.44) ; v3(5319,690) FMC_RX1.G33@5344,715
NetFMC_RX1_G34: FMC_RX1.G34 R119.2 | length 2062.9
  Signals - L8 w4: v1(3453.56,590) 4056,590 4181,715 5344,715 v3(5369,690)
  Bottom Layer - L10 w8: R119.2@3453.56,540 v1(3453.56,590) ; FMC_RX1.G34@5344,665 v3(5369,690)
NetFMC_RX1_G36: FMC_RX1.G36 R57.2 | length 1200.7
  Signals - L8 w4: v1(4205.44,515) 4255.44,465 5057,465 5107,515 5294,515 v3(5319,540)
  Bottom Layer - L10 w8: v3(5319,540) FMC_RX1.G36@5344,565
NetFMC_RX1_G37: FMC_RX1.G37 R55.2 | length 1269.8
  Signals - L8 w4: v1(4205.44,236.38) 4231.06,262 4262,262 4305,305 4305,332 4338,365 5007,365 5107,465 5294,465 v3(5319,490)
  Bottom Layer - L10 w8: v3(5319,490) FMC_RX1.G37@5344,515
NetFMC_RX1_H34: FMC_RX1.H34 R120.2 | length 1975.1
  Signals - L8 w4: v1(3508,390) 3994,390 4219,615 5244,615 v3(5269,640)
  Bottom Layer - L10 w8: R120.2@3453.56,340 3458,340 v1(3508,390) ; v3(5269,640) FMC_RX1.H34@5294,665
NetFMC_RX1_H37: FMC_RX1.H37 R58.2 | length 1096.2
  Signals - L8 w4: v1(4260.56,515) 4310.56,565 5244,565 v3(5269,540)
  Bottom Layer - L10 w8: R58.2@4260.56,493.62 v1(4260.56,515) ; v3(5269,540) FMC_RX1.H37@5294,515
NetFMC_RX1_H38: FMC_RX1.H38 R54.2 | length 1128.1
  Signals - L8 w4: v1(4260.56,236.38) 4295.38,236.38 4324,265 4957,265 5107,415 5244,415 v3(5269,440)
  Bottom Layer - L10 w8: v3(5269,440) FMC_RX1.H38@5294,465
NetJ2_1: J2.1 L31.2 | length 80.3
  Top Layer L1 w19.68: J2.1@2782,1415 L31.2@2862.31,1415
NetJ3_1: J3.1 uWIRE.10 | length 205
  Top Layer L1 w25: J3.1@3401,640 uWIRE.10@3606,640
NetL6_1: L6.1 LMX_LDO.2 R73.2 | length 197.9
  Top Layer L1 w37: L6.1@3820,1939.5 LMX_LDO.2@3820,2040
  Bottom Layer - L10 w51: R73.2@3812.91,2134.44 3812.91,2047.09 LMX_LDO.2@3820,2040
NetL9_1: L9.1 L10.1 L13.1 LMK_LDO.2 R40.2 | length 496.5
  Top Layer L1 w37: L13.1@2860,2040 LMK_LDO.2@3032,2040 ; L10.1@2932,2103 2969,2103 LMK_LDO.2@3032,2040 ; L9.1@3032,1940 LMK_LDO.2@3032,2040
  Bottom Layer - L10 w51: R40.2@3024.91,2135.44 3024.91,2047.09 LMK_LDO.2@3032,2040
NetLD1_1: LD1.1 Status1.1 U6.31 | length 330.1
  Top Layer L1 w9: U6.31@1296.79,2274.95 Status1.1@1493.98,2274.95 LD1.1@1587.93,2181
NetLD2_1: LD2.1 Status2.1 U6.48 | length 473.5
  Top Layer L1 w9: LD2.1@724,2561 Status2.1@794.71,2561 ; Status2.1@795,2561 795,2373 822,2346 970.65,2346 975.92,2340.73 U6.48@975.92,2320.23
NetLF1_1: LF1.1 LF2.1 U6.46 | length 136.1
  Top Layer L1 w5.5: LF2.1@982.86,2386.74 996.86,2372.74 1007.3,2372.74 1015.29,2364.75 U6.46@1015.29,2320.23
  Top Layer L1 w15: LF2.1@982.86,2386.74 LF1.1@982.86,2436.74
NetLF1_2: LF1.2 LF3.2 | length 51.9
  Top Layer L1 w15: LF3.2@875.86,2436.74 LF1.2@927.74,2436.74
NetLF7_2: LF7.2 S1.1 | length 171
  Bottom Layer - L10 w50: S1.1@1246.1,100.2 1358.5,212.6 LF7.2@1370.55,212.6
NetLMKCLK_1: LMKCLK.1 R48.2 R51.2 | length 216.1
  Top Layer L1 w8: R48.2@1301.36,2482.51 R51.2@1338.67,2482.5 LMKCLK.1@1517.5,2482.51
NetOR_T0_1: OR_T0.1 U1.1 | length 71.5
  Top Layer L1 w19.5: U1.1@2912,1232.52 OR_T0.1@2983.47,1232.52
NetOR_T0_2: OR_T0.2 R2.1
  other v1: 3042.53,1232.52
NetOR_T1_1: OR_T1.1 U1.7 | length 169.1
  Top Layer L1 w19.5: U1.7@2862,1047.48 2862,1079 2887,1104 2969.47,1104 OR_T1.1@2983.47,1090
NetOR_T1_2: OR_T1.2 R10.1
  other v1: 3042.53,1090
NetOSCin_1: OSCin.1 R25.1 R30.2 | length 242.7
  Top Layer L1 w8: R30.2@2489.65,1950.78 R25.1@2529.02,1950.78 2599.24,2021 OSCin.1@2599.24,2125
NetR13_1: R13.1 U2.2 | length 62.9
  Top Layer L1 w18: v1(943.26,1202.2) 963.82,1181.65 R13.1@963.82,1175
  Bottom Layer - L10 w9: v1(943.26,1202.2) U2.2@970.47,1202.2
NetR13_2: R13.2 U2.1 | length 64.9
  Top Layer L1 w18: R13.2@908.7,1175 916.22,1182.52 v1(928.26,1182.52)
  Bottom Layer - L10 w9: v1(928.26,1182.52) U2.1@970.47,1182.52
NetR17_2: R17.2 TEMP.2 | length 63.6
  Bottom Layer - L10 w18: R17.2@1758.84,763.41 1768.84,773.41 v1(1818.28,773.41)
NetR26_2: R26.2 R133.1 Y1.1 | length 127.6
  Top Layer L1 w19.68: v1(2911.91,1640) R26.2@2976.47,1640
  Bottom Layer - L10 w18: R133.1@2848.92,1640 v1(2911.91,1640)
NetR31_1: R31.1 R117.1 R124.1 R126.1 U3.12 | length 2085
  Top Layer L1 w8: R124.1@3163,397.13 3163.44,397.57 v1(3163.44,445)
  Top Layer L1 w9: U3.12@1621.08,816.44 1641.28,816.44 v1(1643.28,814.44)
  Signals - L8 w4: v1(1643.28,814.44) 1700.46,871.62 2929.38,871.62 3163.44,637.56 v1(3163.44,445)
  Bottom Layer - L10 w8: v1(1643.28,814.44) 1654.96,814.44 1661.99,821.47 1693.66,821.47 R31.1@1703.72,811.41 ; R117.1@3087.81,392.13 3137.13,392.13 3163.44,418.44 v1(3163.44,445)
NetR32_1: R32.1 R125.1 R127.1 U3.13 | length 2012.8
  Top Layer L1 w9: U3.13@1621.08,836.13 1641.28,836.13 v1(1643.28,838.13)
  Signals - L8 w4: v1(1643.28,838.13) 1621.08,815.93 1621.08,802.92 1646,778 1682,778 1695.44,791.44 2750.89,791.44 2823.33,719 3031,719 3141,609 3141,432 3175.87,397.13 v1(3214.56,397.13)
  Bottom Layer - L10 w8: v1(1643.28,838.13) 1650.15,845 1689.91,845 R32.1@1703.72,858.81
NetR38_2: R38.2 Y1.3 | length 149.8
  Top Layer L1 w8: R38.2@2607.69,1813.68 2720.24,1813.68 Y1.3@2746.56,1840
NetR39_2: R39.2 U5.8 | length 71
  Top Layer L1 w15: R39.2@3218.56,1940 U5.8@3289.57,1940
NetR45_2: R45.2 Status2.2 | length 63.7
  Top Layer L1 w9: Status2.2@854.05,2561.29 R45.2@854.06,2625
NetR47_1: R47.1 R142.2 R143.2 U6.6 | length 395.4
  Top Layer L1 w9: v1(1074.35,1923.69) U6.6@1074.35,1973.77
  Bottom Layer - L10 w8: v1(1074.35,1923.69) 1074.35,1901 R47.1@1085.35,1890 1118.35,1857 1314.44,1857 R142.2@1328.44,1843 R143.2@1328.44,1798.5
NetR52_1: R52.1 USB.2 | length 729.7
  Top Layer L1 w8: USB.2@330.71,813.93 371.71,813.93 379.46,806.18 397.98,806.18 424.17,780 628.63,780 892.94,515.69 914.24,515.69 R52.1@930.24,531.69
NetR52_2: R52.2 U13.7 | length 1639
  Top Layer L1 w8: R52.2@985.36,531.69 1001.36,515.69 2582.63,515.69 2584.47,517.53 U13.7@2616.97,517.53
NetR53_1: R53.1 USB.3 | length 729.7
  Top Layer L1 w8: USB.3@330.71,782.44 371.71,782.44 379.46,790.18 391.36,790.18 417.54,764 622,764 886.31,499.69 914.24,499.69 R53.1@930.24,483.69
NetR53_2: R53.2 U13.8 | length 1639
  Top Layer L1 w8: R53.2@985.36,483.69 1001.36,499.69 2582.63,499.69 2584.47,497.84 U13.8@2616.97,497.84
NetR54_1: R54.1 R118.1 R139.2 SPI.2 U2.59 | length 4287.8
  Top Layer L1 w8: v1(4260.56,291.5) 4273.06,279 4282,279 SPI.2@4346,215
  Signals - L8 w4: v1(1185.19,1097) 1182,1093.81 1182,1044 1190,1036 1190,599 1299,490 2663,490 2720.75,432.25 2720.75,354.25 2816,259 3040,259 3122,177 3374,177 3411,140 4271,140 SPI.2@4346,215
  Bottom Layer - L10 w8: U2.59@1183.07,1147.09 1183.07,1099.12 v1(1185.19,1097) ; SPI.2@4346,215 4396,265 R139.2@4519.44,265
NetR55_1: R55.1 R110.1 SPI.4 U2.56 | length 3994.1
  Top Layer L1 w8: v1(4260.56,340.5) 4320.5,340.5 SPI.4@4346,315
  Signals - L8 w4: v1(1240,1097) 1217,1074 1217,1057 1222,1052 1222,613 1313,522 2751,522 2944,329 3073,329 3125,277 3411,277 3498,190 4014.36,190 4164.86,340.5 v1(4260.56,340.5)
  Bottom Layer - L10 w8: v1(1240,1097) 1242.13,1099.12 U2.56@1242.13,1147.09 ; R55.1@4205.44,291.5 4211.56,291.5 v1(4260.56,340.5)
NetR56_2: R56.2 Status1.2 | length 72.9
  Top Layer L1 w9: Status1.2@1553.03,2274.95 R56.2@1625.94,2274.95
NetR57_1: R57.1 R111.1 R140.2 SPI.6 U2.57 | length 4037.1
  Top Layer L1 w8: v1(4260.56,389.5) 4320.5,389.5 SPI.6@4346,415
  Signals - L8 w4: v1(1236.44,1065) 1236.44,1026.44 1235,1025 1235,963 1320.28,877.72 1320.28,676.72 1459,538 2778,538 2878,438 3009,438 3130,317 3470,317 3497,290 3979,290 4078.5,389.5 v1(4260.56,389.5)
  Bottom Layer - L10 w8: U2.57@1222.44,1147.09 1222.44,1079 v1(1236.44,1065) ; R57.1@4205.44,459.88 4218,447.32 4218,432.06 v1(4260.56,389.5) ; SPI.6@4346,415 4396,365 R140.2@4519.44,365
NetR58_1: R58.1 R109.1 R141.2 SPI.8 U2.58 | length 4351.5
  Top Layer L1 w8: v1(4260.56,438.5) 4273.06,451 4282,451 SPI.8@4346,515
  Signals - L8 w4: v1(1198.76,1075) 1198.76,1054.24 1206,1047 1206,607 1307,506 2681,506 2755,432 2755,358 2833,280 3058,280 3115,223 3372,223 3430,165 4037,165 4188,316 4272,316 4288,332 4288,411.06 v1(4260.56,438.5)
  Bottom Layer - L10 w8: v1(1198.76,1075) 1202.76,1079 U2.58@1202.76,1147.09 ; SPI.8@4346,515 4396,465 R141.2@4519.44,465
NetR65_2: R65.2 U12.9 | length 47
  Top Layer L1 w8: R65.2@4097.24,229 U12.9@4097.24,275.96
NetR66_1: R66.1 U13.14 | length 92.5
  Top Layer L1 w10: R66.1@2536.03,351.73 2564.03,379.73 U13.14@2616.97,379.73
NetR67_2: R67.2 U13.6 | length 164.9
  Top Layer L1 w10: R67.2@2456.47,547.96 2467.22,537.21 U13.6@2616.97,537.21
NetR70_2: R70.2 U7.1 | length 71.1
  Top Layer L1 w18: v1(4726.19,1090) U7.1@4750,1090
  Bottom Layer - L10 w18: v1(4726.19,1090) R70.2@4726.19,1137.29
NetR71_2: R71.2 U8.8 | length 71
  Top Layer L1 w15: R71.2@4006.56,1940 U8.8@4077.57,1940
NetR80_2: R80.2 R89.2 U10.11 | length 96
  Top Layer L1 w13.5: U10.11@3305.86,2582.49 3305.86,2609.67 v1(3310.36,2614.17) 3317.18,2621 3328.1,2621 R80.2@3338.1,2631
  Bottom Layer - L10 w24: R89.2@3310.36,2586.43 v1(3310.36,2614.17)
NetR85_1: R85.1 R88.2 U10.16 | length 55
  Top Layer L1 w8: v1(3108.68,2547.56) 3117.05,2539.18 U10.16@3160.19,2539.18
NetR97_2: R97.2 uWIRE.8 | length 152.4
  Top Layer L1 w8: R97.2@3453.56,540 uWIRE.8@3606,540
NetR98_2: R98.2 uWIRE.6 | length 152.4
  Top Layer L1 w8: R98.2@3453.56,440 uWIRE.6@3606,440
NetR99_1: R99.1 Tdiode.2 U2.64 | length 632.6
  Bottom Layer - L10 w6: U2.64@1084.65,1147.09 1084.65,796.36 1113.35,767.66 1229.62,767.66 Tdiode.2@1270.28,727 ; Tdiode.2@1270,727.28 1279.72,737 R99.1@1333.44,737
NetR100_1: R100.1 Tdiode.1 U2.63 | length 599.4
  Bottom Layer - L10 w6: U2.63@1104.33,1147.09 1104.33,804.52 1121.5,787.34 1230.62,787.34 Tdiode.1@1270.28,827 1280.28,817 R100.1@1333.44,817
NetR101_2: R101.2 uWIRE.4 | length 152.4
  Top Layer L1 w8: R101.2@3453.56,340 uWIRE.4@3606,340
NetR102_2: R102.2 uWIRE.2 | length 152.4
  Top Layer L1 w8: R102.2@3453.56,240 uWIRE.2@3606,240
NetR103_1: R103.1 USB.1 | length 49.6
  Top Layer L1 w19.5: USB.1@330.71,845.43 v1(330.71,867.27)
  Bottom Layer - L10 w16.5: R103.1@330.71,839.52 v1(330.71,867.27)
NetR105_1: R105.1 R108.2 U15.4 | length 102.1
  Bottom Layer - L10 w8: U15.4@2817.32,605.39 R108.2@2817.32,659 R105.1@2817.32,707.44
NetR106_1: R106.1 U13.62 U15.2 | length 307.2
  Top Layer L1 w8: R106.1@2754.2,787.44 2754.2,783.44 2727.2,756.44 U13.62@2727.2,706.5 2727.2,600.8 2773.8,554.2 v1(2817.32,554.2)
NetR107_1: R107.1 U13.63 U15.1 | length 332.3
  Top Layer L1 w8: R107.1@2706.2,787.44 2707.52,786.13 U13.63@2707.52,706.5 2707.52,591.48 2770.39,528.61 v1(2817.32,528.61)
NetR108_1: R108.1 U13.61 U15.3 | length 301
  Top Layer L1 w8: U13.61@2746.89,706.5 2746.89,614.11 2781.2,579.8 v1(2817.32,579.8)
  Bottom Layer - L10 w8: v1(2817.32,579.8) 2854.8,579.8 2872.44,597.44 R108.1@2872.44,659
NetR112_2: R112.2 USB_PWR.2 | length 64
  Top Layer L1 w16.5: R112.2@2416.91,245.68 USB_PWR.2@2480.91,245.68
NetR134_2: R134.2 R135.2 U2.30 | length 362.2
  Bottom Layer - L10 w8: U2.30@1242.13,1532.91 1242.13,1731.13 1265,1754 R134.2@1328.44,1754 R135.2@1376.64,1705.8
NetR145_1: R145.1 U4.25 | length 120.3
  Top Layer L1 w8: U4.25@2426.72,1721.1 2426.72,1693.7 2453.93,1666.5 R145.1@2508.33,1666.5
NetR149_2: R149.2 U4.24 | length 232.4
  Top Layer L1 w8: U4.24@2401.13,1695.51 2401.13,1671.16 2435.2,1637.09 2454.33,1637.09 2462.24,1629.19 2462.24,1547.68 R149.2@2496.24,1513.68
NetR150_2: R150.2 Vtune.1 | length 48.1
  Top Layer L1 w8: R150.2@2587.98,1513.68 2602.55,1513.68 Vtune.1@2626.24,1490
NetR151_2: R151.2 R152.1 U4.19 | length 203.4
  Top Layer L1 w8: R152.1@2200.56,1565 v1(2200.56,1615) ; v1@2302.71,1664.93 U4.19@2302.71,1695.51
  Bottom Layer - L10 w8: v1(2200.56,1615) 2252.78,1615 v1@2302.71,1664.93
  other v1: 2302.71,1664.07
NetR154_2: R154.2 U4.32 | length 365.4
  Top Layer L1 w8: R154.2@2395,2140 v1(2445,2090) ; U4.32@2426.72,1858.9 2439.27,1858.9 v1(2458.17,1840)
  Bottom Layer - L10 w8: v1(2445,2090) 2445,1998 2458.17,1984.83 v1(2458.17,1840)
NetRSV_2: RSV.2 U2.66 | length 445.1
  Bottom Layer - L10 w9: RSV.2@1045.28,702 U2.66@1045.28,1147.09
"NetTs ADD1_2": "Ts ADD1.2" U3.9 | length 166.4
  Top Layer L1 w10: 1617.28,653 1667.28,703 1667.28,749 1658.89,757.39 U3.9@1621.08,757.39
NetU2_3: U2.3 Vcmo.2 | length 315.6
  Bottom Layer - L10 w9: Vcmo.2@857.78,977 890,1009.22 890,1182.5 929.39,1221.89 U2.3@970.47,1221.89
NetU2_68: U2.68 Vbg.2 | length 179.7
  Bottom Layer - L10 w9: Vbg.2@982.78,977 1005.91,1000.13 U2.68@1005.91,1147.09
NetU12_3: U12.3 U13.16 | length 1584.7
  Top Layer L1 w8: v1(3771.14,428.91) 3796.14,403.91 U12.3@3876.76,403.91
  Top Layer L1 w10: v1(2616.97,287) U13.16@2616.97,340.36
  Bottom Layer - L10 w8: v1(2616.97,287) 2746.97,157 3614,157 3656,199 3656,360.71 3685.29,390 3732.23,390 v1(3771.14,428.91)
NetU12_4: U12.4 U13.17 | length 1495
  Top Layer L1 w8: v1(2680.83,189.03) 2687.83,196.03 U13.17@2687.83,269.5 ; v1(3771.14,264) 3771.14,354.32 3795.14,378.32 U12.4@3876.76,378.32
  Bottom Layer - L10 w8: v1(2680.83,189.03) 2736.86,133 3705,133 3771.14,199.14 v1(3771.14,264)
NetU12_5: U12.5 U13.18 | length 1542.4
  Top Layer L1 w8: v1(2686.68,149.19) 2707.52,170.03 U13.18@2707.52,269.5 ; v1(3795.14,240) 3795.14,328.73 3819.14,352.73 U12.5@3900.76,352.73
  Bottom Layer - L10 w8: v1(2686.68,149.19) 2726.86,109 3714.94,109 3795.14,189.2 v1(3795.14,240)
NetU12_6: U12.6 U13.19 | length 1541.7
  Top Layer L1 w8: v1(2692.52,109.34) 2727.2,144.03 U13.19@2727.2,269.5 ; v1(3819.14,216) 3819.14,303.14 3843.14,327.14 U12.6@3876.76,327.14
  Bottom Layer - L10 w8: v1(2692.52,109.34) 2716.86,85 3724.88,85 3819.14,179.26 v1(3819.14,216)
NetU13_27: U13.27 U18.2 | length 74.8
  Top Layer L1 w8: v1(2864.68,335.96) 2884.68,315.96 U13.27@2884.68,269.5
NetU13_29: U13.29 U18.1 | length 75.6
  Top Layer L1 w8: v1(2902.07,335.96) 2924.05,313.98 U13.29@2924.05,269.5
PG_C2M_RX: FMC_RX1.D1 PG_RX1.1 | length 692.9
  Signals - L3 w18: PG_RX1.1@4994,2559 5094,2459 5244,2459 5344,2359 5344,2323 5352,2315 5494,2315 v3(5519,2340)
  Bottom Layer - L10 w18: FMC_RX1.D1@5494,2315 v3(5519,2340)
PG_M2C_RX: FMC_RX1.F1 PG_RX1.2 RR6.1 | length 609.2
  Top Layer L1 w18: PG_RX1.2@4894,2559 4994,2459 5244,2459 5349.12,2353.88 RR6.1@5349.12,2340 v1(5369,2340)
  Bottom Layer - L10 w18: v1(5369,2340) FMC_RX1.F1@5394,2315
SYNC_N: FMC_RX1.G13 R20.2 | length 4335.8
  Top Layer L1 w8: R20.2@1107,1707.98 1098,1716.98 1098,1737 1123.5,1762.5 1421.55,1762.5 v1(1432.55,1751.5)
  Signals - L6 w4: v1(1432.55,1751.5) 1442.05,1761 5319,1761 5327,1753 5327,1748 v3(5319,1740)
  Bottom Layer - L10 w8: v3(5319,1740) FMC_RX1.G13@5344,1715
SYNC_P: FMC_RX1.G12 R19.2 | length 4335.9
  Top Layer L1 w8: R19.2@1080,1707.98 1082,1709.98 1082,1743.63 1116.87,1778.5 v1(1432.55,1778.5)
  Signals - L6 w4: v1(1432.55,1778.5) 1442.05,1769 5298,1769 v3(5319,1790)
  Bottom Layer - L10 w8: v3(5319,1790) FMC_RX1.G12@5344,1765
SYNC_SE: FMC_RX1.H31 R134.1 R143.1 | length 5173.3
  Signals - L6 w4: v1(1470,1619) 1523,1566 1632,1566 1791,1407 1791,1321 1797,1315 2377,1315 ; 2377,1314 2448,1243 2448,1153 2461,1140 2493,1140 2506,1153 2506,1176 2595,1265 4999,1265 5149,1115 5481,1115 5494,1102 5494,878 5481,865 5294,865 v3(5269,840)
  Bottom Layer - L10 w8: R143.1@1383.56,1798.5 R134.1@1383.56,1754 1432.36,1705.2 1432.36,1656.64 v1(1470,1619) ; v3(5269,840) FMC_RX1.H31@5294,815
SYNC~/TMST_N: R20.1 R21.1 R23.1 U2.23 | length 178.8
  Top Layer L1 w8: R20.1@1107.99,1681.01 1110.01,1678.99 R23.1@1135,1678.99
  Bottom Layer - L10 w8: U2.23@1104.33,1532.91 1102.49,1534.76 1102.49,1675.32 v1(1107.99,1680.82)
SYNC~/TMST_P: R18.1 R19.1 R22.1 U2.22 | length 179
  Top Layer L1 w8: R22.1@1081.01,1653 R19.1@1080.99,1681.01
  Bottom Layer - L10 w8: v1(1080.99,1680.82) 1086.49,1675.31 1086.49,1534.76 U2.22@1084.65,1532.91
SYSREFRX_N: FMC_RX1.G10 R61.2 | length 4198.7
  Signals - L8 w4: v1(1238.99,1837.32) 1225.99,1850.32 1225.99,1858.13 1278.86,1911 5314,1911 5324,1901 5324,1895 v3(5319,1890)
  Bottom Layer - L10 w8: v3(5319,1890) FMC_RX1.G10@5344,1865
SYSREFRX_P: FMC_RX1.G9 R62.2 | length 4198.4
  Signals - L8 w4: v1(1204.99,1837.32) 1217.99,1850.32 1217.99,1861.45 1275.54,1919 5298,1919 v3(5319,1940)
  Bottom Layer - L10 w8: v3(5319,1940) FMC_RX1.G9@5344,1915
SYSREFTX_N: C37.2 R43.2 | length 640.2
  Top Layer L1 w8: R43.2@777.1,2106 759.1,2124 749.04,2124 732.23,2107.19 732.23,1982.37 917.23,1797.37 1003.25,1797.37 1037.96,1762.66 1037.96,1709.04 C37.2@1042,1705
SYSREFTX_P: C35.2 R44.2 | length 664.5
  Top Layer L1 w8: R44.2@777.1,2140 742.41,2140 716.23,2113.81 716.23,1975.74 753,1938.97 910.6,1781.37 996.62,1781.37 1007.93,1770.05 1021.96,1756.03 C35.2@1021.96,1698.02
SYSRF_N: C37.1 C91.1 U2.20 | length 141.9
  Bottom Layer - L10 w8: U2.20@1045.28,1532.91 1043.43,1534.76 1043.43,1666.32 v1(1048.93,1671.82)
SYSRF_P: C35.1 C90.1 U2.19 | length 141.9
  Bottom Layer - L10 w8: C90.1@1021.93,1671.82 1027.43,1666.31 1027.43,1534.76 U2.19@1025.59,1532.91
  other v1: 1021.93,1672.01
TCRIT1: R16.1 R17.1 TCRIT1.1 U3.10 | length 266.6
  Top Layer L1 w9: U3.10@1621.08,777.07 1691.06,777.07 v1(1703.72,764.41) 1755.13,713 1776.28,713 TCRIT1.1@1836.28,653
TCRIT2: R15.1 TCRIT2.1 U3.11 | length 390.5
  Top Layer L1 w9: U3.11@1621.08,796.76 1666.28,796.76 v1(1668.28,798.76) 1691.06,798.76 R15.1@1703.72,811.41
  Signals - L6 w9: v1(1668.28,798.76) 1724.49,798.76 1798.25,725 TCRIT2.1@1939.5,725
TCRIT3: R14.1 TCRIT3.1 U3.14 | length 163.8
  Top Layer L1 w9: U3.14@1621.08,855.81 1703.72,855.81 TCRIT3.1@1703.72,937
TMST_N: R21.2 TMST-.1 | length 1401.2
  Bottom Layer - L10 w8: TMST-.1@100,2330.16 210,2330.16 228.2,2311.95 228.2,2120.03 246.58,2101.66 506.31,2101.66 808.6,1799.37 1054.26,1799.37 1101.5,1752.13 1101.5,1713.48 R21.2@1107.99,1706.99
TMST_P: R18.2 TMST+.1 | length 1400.8
  Bottom Layer - L10 w8: TMST+.1@100,1830.16 210,1830.16 228.2,1848.36 228.2,2067.28 246.58,2085.66 499.68,2085.66 801.98,1783.37 1047.63,1783.37 1085.5,1745.5 1085.5,1711.5 R18.2@1080.99,1706.99
TRF3765_STROBE: R97.1 R113.1 R116.2 R119.1 U4.5 | length 2323.1
  Top Layer L1 w8: U4.5@2322.39,1884.49 v1(2322.39,1990) ; R116.2@3351.56,498 R113.1@3351.56,540 R97.1@3398.44,540
  Signals - L3 w4: v1(2322.39,1990) 2322.39,1890 2312.55,1880.16 2312.55,1676.45 2378,1611 2378,1405 2497,1286 2649,1286 2977,958 3119,958 3258,819 v1(3326,819)
  Signals - L6 w4: v1(3326,819) 3326,590.56 v1(3376.56,540)
  Bottom Layer - L10 w8: v1(3376.56,540) R119.1@3398.44,540
TRF_OUTA_N: C112.2 R157.1 R159.2 U17.6 | length 1288.2
  Top Layer L1 w8: v1(1616.54,1703.5) U17.6@1668.84,1703.5
  Bottom Layer - L10 w8: C112.2@1224.67,2456.69 R157.1@1224.67,2519 1233.67,2528 1233.67,2551.96 1254.71,2573 1331.63,2573 1414.25,2490.38 1480.13,2490.38 1513.5,2457 1513.5,1799.46 1609.46,1703.5 v1(1616.54,1703.5)
TRF_OUTA_P: C113.2 R156.1 R158.2 U17.7 | length 1287.7
  Top Layer L1 w8: v1(1616.54,1653.5) U17.7@1668.84,1653.5
  Bottom Layer - L10 w8: C113.2@1258.67,2456.69 R156.1@1258.67,2519 1249.67,2528 1249.67,2545.33 1261.34,2557 1325,2557 1407.62,2474.38 1473.5,2474.38 1497.5,2450.38 1497.5,1792.83 1616.54,1673.8 v1(1616.54,1653.5)
TRF_OUTB_N: C33.2 C83.2 R36.2 | length 1614.8
  Top Layer L1 w8: C33.2@807.59,1481.45 797.14,1471 788.04,1471 760,1499.04 760,1595.37 794.63,1630 801.95,1630 811,1620.95 v1(811,1603.65) ; v1@1798,1792.7 1787,1803.7 1787,1854.5 1836.32,1903.81 1905.42,1903.81 R36.2@1926.05,1883.18 C83.2@1958.36,1883.18
  Signals - L8 w4: v1(811,1603.65) 811,1628.65 818,1635.65 1134.58,1635.65 1158.94,1660 1532.31,1660 1546.81,1674.5 1721.81,1674.5 1779,1731.69 1779,1771 v1(1798,1790)
TRF_OUTB_P: C32.2 C75.2 R29.2 | length 1614.6
  Top Layer L1 w8: C32.2@807.59,1454.45 807.04,1455 781.41,1455 744,1492.41 744,1602 792.65,1650.65 v1(811,1650.65) ; v1(1771,1790) 1771,1861.13 1829.69,1919.81 R29.2@1926.05,1919.81 C75.2@1958.36,1919.81
  Signals - L8 w4: v1(811,1650.65) 818,1643.65 1131.27,1643.65 1155.62,1668 1529,1668 1543.5,1682.5 1718.5,1682.5 1771,1735 v1(1771,1790)
U2-67: U2.67 | length 14.1
  Bottom Layer - L10 w9: 1025.59,1133 U2.67@1025.59,1147.09
U6-3: U6.3 | length 20.5
  Top Layer L1 w9: 1015.29,1953.27 U6.3@1015.29,1973.77
U6-4: U6.4 | length 20.5
  Top Layer L1 w9: 1034.98,1953.27 U6.4@1034.98,1973.77
U6-7: U6.7 | length 20.5
  Top Layer L1 w9: 1094.03,1953.27 U6.7@1094.03,1973.77
U6-8: U6.8 | length 20.5
  Top Layer L1 w9: 1113.72,1953.27 U6.8@1113.72,1973.77
U6-9: U6.9 | length 20.5
  Top Layer L1 w9: 1133.4,1953.27 U6.9@1133.4,1973.77
U6-15: U6.15 | length 20.5
  Top Layer L1 w9: 1251.51,1953.27 U6.15@1251.51,1973.77
U6-16: U6.16 | length 20.5
  Top Layer L1 w9: 1271.2,1953.27 U6.16@1271.2,1973.77
U6-22: U6.22 | length 20.5
  Top Layer L1 w9: U6.22@1296.79,2097.79 1317.29,2097.79
U6-23: U6.23 | length 20.5
  Top Layer L1 w9: U6.23@1296.79,2117.47 1317.29,2117.47
U6-27: U6.27 | length 20.5
  Top Layer L1 w9: U6.27@1296.79,2196.21 1317.29,2196.21
U6-28: U6.28 | length 20.5
  Top Layer L1 w9: U6.28@1296.79,2215.9 1317.29,2215.9
U6-29: U6.29 | length 20.5
  Top Layer L1 w9: U6.29@1296.79,2235.58 1317.29,2235.58
U6-30: U6.30 | length 20.5
  Top Layer L1 w9: U6.30@1296.79,2255.27 1317.29,2255.27
U6-32: U6.32 | length 20.5
  Top Layer L1 w9: U6.32@1296.79,2294.64 1317.29,2294.64
U6-40: U6.40 | length 20.5
  Top Layer L1 w9: U6.40@1133.4,2320.23 1133.4,2340.73
U6-41: U6.41 | length 20.5
  Top Layer L1 w9: U6.41@1113.72,2320.23 1113.72,2340.73
U6-49: U6.49 | length 20.5
  Top Layer L1 w9: 929.83,2294.64 U6.49@950.33,2294.64
U6-50: U6.50 | length 20.5
  Top Layer L1 w9: 929.83,2274.95 U6.50@950.33,2274.95
U6-51: U6.51 | length 20.5
  Top Layer L1 w9: 929.83,2255.27 U6.51@950.33,2255.27
U6-52: U6.52 | length 20.5
  Top Layer L1 w9: 929.83,2235.58 U6.52@950.33,2235.58
U6-58: U6.58 | length 20.5
  Top Layer L1 w9: 929.83,2117.47 U6.58@950.33,2117.47
U6-59: U6.59 | length 20.5
  Top Layer L1 w9: 929.83,2097.79 U6.59@950.33,2097.79
U6-60: U6.60 | length 20.5
  Top Layer L1 w9: 929.83,2078.1 U6.60@950.33,2078.1
U6-61: U6.61 | length 20.5
  Top Layer L1 w9: 929.83,2058.42 U6.61@950.33,2058.42
U6-62: U6.62 | length 20.5
  Top Layer L1 w9: 929.83,2038.73 U6.62@950.33,2038.73
U6-63: U6.63 | length 20.5
  Top Layer L1 w9: 929.83,2019.05 U6.63@950.33,2019.05
VADJ_RX: FMC_RX1.E39 FMC_RX1.F40 FMC_RX1.G39 FMC_RX1.H40 RR6.2 RR7.1 VADJ_RX.1 | length 2487.1
  Top Layer L1 w18: VADJ_RX.1@4994,2315 5294,2315 ; RR6.2@5294,2340 5294,2315 ; v1(5319,390) 5294,390 5294,2315
  Bottom Layer - L10 w18: FMC_RX1.H40@5294,365 v1(5319,390) FMC_RX1.G39@5344,415 v3(5369,390) FMC_RX1.F40@5394,365 v3(5419,390) FMC_RX1.E39@5444,415
VCC2: C103.1 L2.2 U6.17 | length 120.8
  Top Layer L1 w9: U6.17@1296.79,1999.36 v1(1331.87,1999.36)
  Bottom Layer - L10 w18: L2.2@1313,1932.5 C103.1@1313,1999.36 v1(1331.87,1999.36)
VCC3: C106.1 L4.2 U6.21 | length 100.4
  Top Layer L1 w9: U6.21@1296.79,2078.1 v1(1331.87,2078.1)
  Bottom Layer - L10 w18: C106.1@1313,2078.1 v1(1331.87,2078.1) 1363.23,2078.1 L4.2@1373.92,2067.42
VCC4: C111.1 L19.2 U6.26 | length 100.4
  Top Layer L1 w9: U6.26@1296.79,2176.53 v1(1331.87,2176.53)
  Bottom Layer - L10 w18: C111.1@1313,2176.53 v1(1331.87,2176.53) 1363.23,2176.53 L19.2@1373.92,2187.21
VCC6: C105.1 L3.2 U6.36 | length 112.2
  Top Layer L1 w9: U6.36@1212.14,2320.23 v1(1212.14,2355.31)
  Bottom Layer - L10 w18: L3.2@1170.95,2396.5 v1(1212.14,2355.31) C105.1@1212.14,2336.45
VCC9: C110.1 L5.2 U6.45 | length 95.1
  Top Layer L1 w9: U6.45@1034.98,2320.23 v1(1034.98,2355.31)
  Bottom Layer - L10 w18: C110.1@1034.98,2336.45 v1(1034.98,2355.31) L5.2@1034.98,2396.5
VCC11: C120.1 L21.2 U6.53 | length 93.7
  Top Layer L1 w9: v1(915.24,2215.9) U6.53@950.33,2215.9
  Bottom Layer - L10 w18: L21.2@875.5,2215.9 v1(915.24,2215.9) C120.1@934.11,2215.9
VCC12: C121.1 L22.2 U6.64 | length 93.7
  Top Layer L1 w9: v1(915.24,1999.36) U6.64@950.33,1999.36
  Bottom Layer - L10 w18: L22.2@875.5,1999.36 v1(915.24,1999.36) C121.1@934.11,1999.36
VIN_N: C5.1 C6.2 U2.9 | length 139.9
  Bottom Layer - L10 w8: v1(833.57,1343.66) 839.07,1338.16 968.63,1338.16 U2.9@970.47,1340
VIN_P: C1.1 C3.1 U2.8 | length 139.9
  Bottom Layer - L10 w8: v1(833.57,1316.66) 839.07,1322.16 968.63,1322.16 U2.8@970.47,1320.31
VIO_1P2VA: C39.1 C40.1 C41.2 C42.2 C43.2 C44.2 C45.2 C46.2 C47.2 C48.1 C177.1 C188.1 L15.2 U2.6 U2.11 U2.14 U2.17 U2.18 U2.21 U2.65 VA12.2 | length 654.1
  Top Layer L1 w16: C41.2@910.64,1280.94 v1(928.26,1280.94) ; C42.2@910.64,1379.37 v1(928.26,1379.37) ; C44.2@925.64,1497.48 v1(943.26,1497.48) ; v1(943.26,1438.43) C43.2@960.88,1438.43
  Top Layer L1 w18: v1(943.26,1497.48) 943.26,1560.13 v1(1005.91,1560.13) v1(1064.96,1560.13)
  Top Layer L1 w31.5: v1(2679.56,2406.01) v1(2741,2406.01) v1(2741,2341.5)
  Bottom Layer - L10 w9: v1(928.26,1280.94) U2.6@970.47,1280.94 ; v1(928.26,1379.37) U2.11@970.47,1379.37 ; v1(943.26,1438.43) U2.14@970.47,1438.43 ; v1(943.26,1497.48) U2.17@970.47,1497.48 ; U2.18@1005.91,1532.91 v1(1005.91,1560.13) ; v1(1064.96,1119.87) U2.65@1064.96,1147.09 ; U2.21@1064.96,1532.91 v1(1064.96,1560.13)
  Bottom Layer - L10 w16: v1(1005.91,1560.13) C45.2@1005.91,1577.75 ; C47.2@1064.96,1102.25 v1(1064.96,1119.87) ; v1(1064.96,1560.13) C46.2@1064.96,1577.75
VIO_1P2VD: C60.1 C61.1 C62.2 C63.2 C64.2 C65.2 C66.2 C67.2 C68.2 C69.2 C70.2 C71.2 C72.1 C95.2 C96.2 C189.1 C197.1 L16.2 NCO.2 NCO.4 NCO.6 RSV.3 U2.28 U2.31 U2.34 U2.37 U2.40 U2.43 U2.46 U2.49 U2.52 U2.55 VD12.2 | length 917.5
  Top Layer L1 w16: C71.2@1202.76,1542.5 v1(1202.76,1560.13)
  Top Layer L1 w18: v1(1261.81,1119.87) v1(1320.87,1119.87) ; v1(1261.81,1560.13) v1(1320.87,1560.13) 1368.25,1512.74 1368.25,1511.4 1383.51,1496.14 v1(1383.51,1458.11)
  Top Layer L1 w31.5: v1(2829,2292.5) v1(2829,2406.01)
  Bottom Layer - L10 w9: U2.28@1202.76,1532.91 v1(1202.76,1560.13) ; v1(1261.81,1119.87) U2.55@1261.81,1147.09 ; U2.31@1261.81,1532.91 v1(1261.81,1560.13) ; v1(1320.87,1119.87) U2.52@1320.87,1147.09 ; U2.34@1320.87,1532.91 v1(1320.87,1560.13) ; U2.49@1356.3,1221.89 v1(1383.51,1221.89) ; U2.46@1356.3,1280.94 v1(1383.51,1280.94) ; U2.43@1356.3,1340 v1(1383.51,1340) ; U2.40@1356.3,1399.06 v1(1383.51,1399.06) ; U2.37@1356.3,1458.11 v1(1383.51,1458.11)
  Bottom Layer - L10 w16: C62.2@1261.81,1102.25 v1(1261.81,1119.87) ; v1(1261.81,1560.13) C70.2@1261.81,1577.75 ; C63.2@1320.87,1102.25 v1(1320.87,1119.87) ; v1(1320.87,1560.13) C69.2@1320.87,1577.75 ; v1(1383.51,1221.89) C64.2@1401.13,1221.89 ; v1(1383.51,1280.94) C65.2@1401.13,1280.95 ; v1(1383.51,1340) C66.2@1401.13,1340 ; v1(1383.51,1399.06) C67.2@1401.13,1399.05 ; v1(1383.51,1458.11) C68.2@1401.13,1458.11
  Bottom Layer - L10 w18: C96.2@1373,1023.19 VD12.2@1373,1078 ; NCO.6@1971.5,1190 C95.2@2026.31,1190
  other v1: 2829,2341.5
VIO_1P4: 1V2ADC_INT.1 C176.1 C190.1 C219.1 C221.1 C224.1 C225.1 L14.2 R83.1 | length 253.7
  Top Layer L1 w19.5: C219.1@3228.53,1090 v1(3271.85,1090)
  Top Layer L1 w31.5: v1(3271.85,1090) L14.2@3271.85,1143.5
  Bottom Layer - L10 w24: C190.1@3271.85,1084 v1@3271.85,1143.5
  Bottom Layer - L10 w51: R83.1@3223.18,2210.56 3223.18,2297.91 1V2ADC_INT.1@3230.27,2305
  other v1: 3368.32,1090 3271.85,1140 3223.68,1790 3368.32,1790
VIO_1P4V: C175.1 C182.1 C183.1 L12.2 L14.1 R82.2 | length 675.5
  Bottom Layer - L10 w10: C183.1@3271.85,1283 3288,1299.15 3288,1344.56 R82.2@3687,1743.56
  Bottom Layer - L10 w24: v1@3271.85,1240 C183.1@3271.85,1283
  other v1: 3271.85,1240 3271.85,1290 3687,1740
VIO_1P9V: C49.1 C50.1 C51.2 C52.2 C53.2 C54.2 C55.2 C56.2 C57.2 C58.2 C59.1 C130.1 C191.1 C202.1 L18.2 R39.1 R71.1 R80.1 R123.2 U2.4 U2.7 U2.10 U2.13 U2.24 U2.27 U2.60 U2.62 U12.15 VA19.2 | length 3113.2
  Top Layer L1 w13: U12.15@4097.24,429.5 4133.5,429.5 v1(4139,435)
  Top Layer L1 w15: v1(3112,2207) 3082,2177 3082,1990 3132,1940 R39.1@3163.44,1940 ; v1(3900,2207) 3870,2177 3870,1990 3920,1940 v1(3951.44,1940)
  Top Layer L1 w16: C51.2@910.64,1241.57 v1(928.26,1241.57) ; C54.2@910.64,1418.74 v1(928.26,1418.74) ; v1(943.26,1359.68) C53.2@960.88,1359.68
  Top Layer L1 w18: v1(943.26,1300.63) 953.58,1310.95 C52.2@963.57,1310.95
  Top Layer L1 w24: v1(4139,435) 4157,453 C130.1@4157,462.75 ; v1(4157,235.22) R123.2@4157,262.97
  Top Layer L1 w31.5: v1(4448.5,2602.93) 4448.5,2546.49 v1(4453.5,2541.49)
  Bottom Layer - L10 w9: v1(928.26,1241.57) U2.4@970.47,1241.57 ; v1(928.26,1418.74) U2.13@970.47,1418.74 ; v1(943.26,1300.63) U2.7@970.47,1300.63 ; v1(943.26,1359.68) U2.10@970.47,1359.68 ; v1(1124.02,1119.87) U2.62@1124.02,1147.09 ; U2.24@1124.02,1532.91 v1(1124.02,1560.13) ; v1(1163.39,1119.87) U2.60@1163.39,1147.09 ; U2.27@1183.07,1532.91 v1(1183.07,1575.13)
  Bottom Layer - L10 w16: C58.2@1124.02,1102.25 v1(1124.02,1119.87) ; v1(1124.02,1560.13) C55.2@1124.02,1577.75 ; C57.2@1163.39,1102.25 v1(1163.39,1119.87) ; v1(1183.07,1575.13) C56.2@1183.07,1592.75
  Bottom Layer - L10 w24: v1(3951.44,1940) 3980,1911.44 3980,1830 3951,1801 3951,1683.97 3934.61,1667.58 3934.61,1579.64 3949.25,1565 4019.97,1565 4034.61,1550.36 4034.61,651.39 4129,557 4129,445 v1(4139,435) 4157,417 v1(4157,235.22)
  other v1: 814,1103.87 3393.22,2631
VIO_2P25: 1V9INT.1 C199.1 C203.1 C222.1 C223.1 C226.1 C227.1 L20.2 R95.1 | length 258.5
  Top Layer L1 w19.5: v1(4486.15,1090) v1(4534.31,1090)
  Top Layer L1 w31.5: v1(4486.15,1090) L20.2@4486.15,1143.5
  Bottom Layer - L10 w24: C203.1@4486.15,1084 v1@4486.15,1143.5
  Bottom Layer - L10 w51: 1V9INT.1@4234,2269.07 4241.09,2261.98 R95.1@4328.44,2261.98
  other v1: 4145.69,1090 4486.15,1140 4145.69,1790 4322.32,1790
